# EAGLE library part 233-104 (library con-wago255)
WAGO Cage Clamp

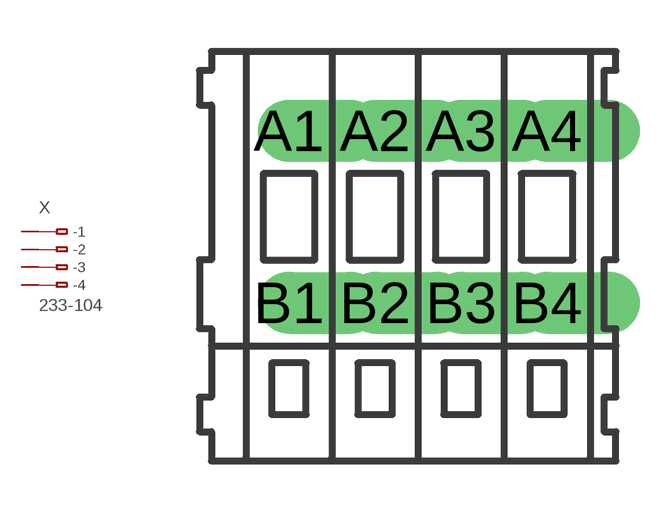
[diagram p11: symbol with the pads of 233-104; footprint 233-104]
Designator prefix X

## 233-104  [233-104]
A1  -1  pas
A2  -2  pas
A3  -3  pas
A4  -4  pas
B1  B-1  pas
B2  B-2  pas
B3  B-3  pas
B4  B-4  pas

## Footprint 233-104 (pad centres in mm)
WAGO Cage Clamp
drill 1.2 offset: A1 -3.75,2.5; A2 -1.25,2.5; A3 1.25,2.5; A4 3.75,2.5; B1 -3.75,-2.5; B2 -1.25,-2.5; B3 1.25,-2.5; B4 3.75,-2.5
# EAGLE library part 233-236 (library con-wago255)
WAGO Cage Clamp

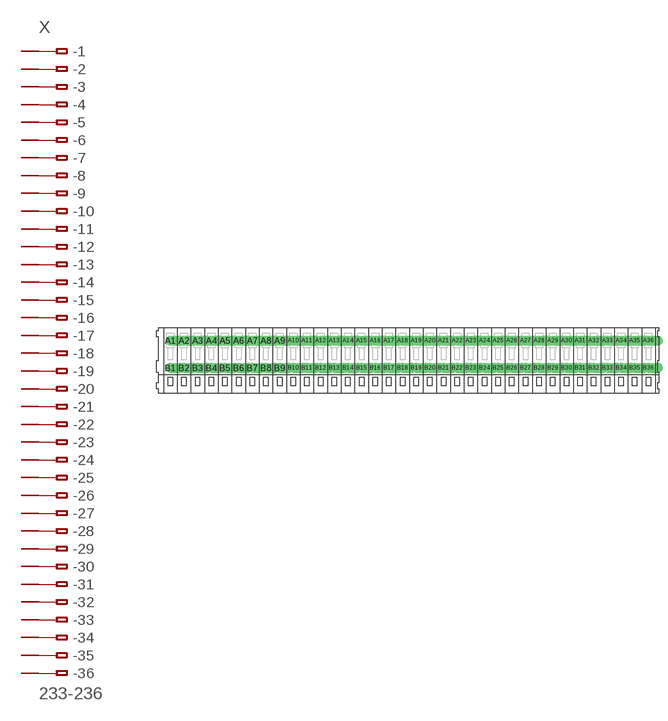
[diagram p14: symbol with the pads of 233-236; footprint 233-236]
Designator prefix X

## 233-236  [233-236]
A1  -1  pas
A2  -2  pas
A3  -3  pas
A4  -4  pas
A5  -5  pas
A6  -6  pas
A7  -7  pas
A8  -8  pas
A9  -9  pas
A10  -10  pas
A11  -11  pas
A12  -12  pas
A13  -13  pas
A14  -14  pas
A15  -15  pas
A16  -16  pas
A17  -17  pas
A18  -18  pas
A19  -19  pas
A20  -20  pas
A21  -21  pas
A22  -22  pas
A23  -23  pas
A24  -24  pas
A25  -25  pas
A26  -26  pas
A27  -27  pas
A28  -28  pas
A29  -29  pas
A30  -30  pas
A31  -31  pas
A32  -32  pas
A33  -33  pas
A34  -34  pas
A35  -35  pas
A36  -36  pas
B1  B-1  pas
B2  B-2  pas
B3  B-3  pas
B4  B-4  pas
B5  B-5  pas
B6  B-6  pas
B7  B-7  pas
B8  B-8  pas
B9  B-9  pas
B10  B-10  pas
B11  B-11  pas
B12  B-12  pas
B13  B-13  pas
B14  B-14  pas
B15  B-15  pas
B16  B-16  pas
B17  B-17  pas
B18  B-18  pas
B19  B-19  pas
B20  B-20  pas
B21  B-21  pas
B22  B-22  pas
B23  B-23  pas
B24  B-24  pas
B25  B-25  pas
B26  B-26  pas
B27  B-27  pas
B28  B-28  pas
B29  B-29  pas
B30  B-30  pas
B31  B-31  pas
B32  B-32  pas
B33  B-33  pas
B34  B-34  pas
B35  B-35  pas
B36  B-36  pas

## Footprint 233-236 (pad centres in mm)
WAGO Cage Clamp
drill 1.2 offset: A1 -43.75,2.5; A2 -41.25,2.5; A3 -38.75,2.5; A4 -36.25,2.5; A5 -33.75,2.5; A6 -31.25,2.5; A7 -28.75,2.5; A8 -26.25,2.5; A9 -23.75,2.5; A10 -21.25,2.5; A11 -18.75,2.5; A12 -16.25,2.5; A13 -13.75,2.5; A14 -11.25,2.5; A15 -8.75,2.5; A16 -6.25,2.5; A17 -3.75,2.5; A18 -1.25,2.5; A19 1.25,2.5; A20 3.75,2.5; A21 6.25,2.5; A22 8.75,2.5; A23 11.25,2.5; A24 13.75,2.5; A25 16.25,2.5; A26 18.75,2.5; A27 21.25,2.5; A28 23.75,2.5; A29 26.25,2.5; A30 28.75,2.5; A31 31.25,2.5; A32 33.75,2.5; A33 36.25,2.5; A34 38.75,2.5; A35 41.25,2.5; A36 43.75,2.5; B1 -43.75,-2.5; B2 -41.25,-2.5; B3 -38.75,-2.5; B4 -36.25,-2.5; B5 -33.75,-2.5; B6 -31.25,-2.5; B7 -28.75,-2.5; B8 -26.25,-2.5; B9 -23.75,-2.5; B10 -21.25,-2.5; B11 -18.75,-2.5; B12 -16.25,-2.5; B13 -13.75,-2.5; B14 -11.25,-2.5; B15 -8.75,-2.5; B16 -6.25,-2.5; B17 -3.75,-2.5; B18 -1.25,-2.5; B19 1.25,-2.5; B20 3.75,-2.5; B21 6.25,-2.5; B22 8.75,-2.5; B23 11.25,-2.5; B24 13.75,-2.5; B25 16.25,-2.5; B26 18.75,-2.5; B27 21.25,-2.5; B28 23.75,-2.5; B29 26.25,-2.5; B30 28.75,-2.5; B31 31.25,-2.5; B32 33.75,-2.5; B33 36.25,-2.5; B34 38.75,-2.5; B35 41.25,-2.5; B36 43.75,-2.5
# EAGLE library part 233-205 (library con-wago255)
WAGO Cage Clamp

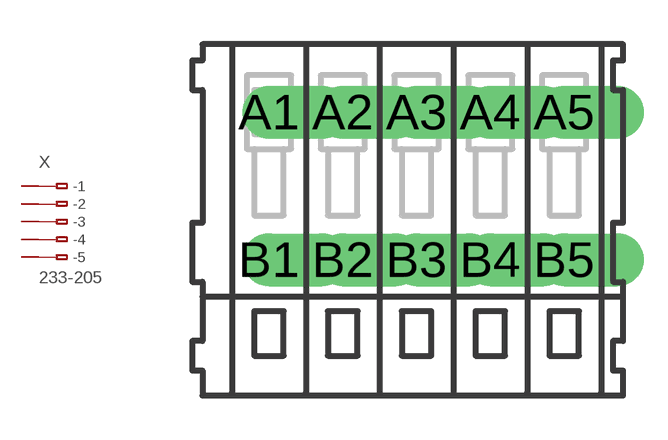
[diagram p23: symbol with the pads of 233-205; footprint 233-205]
Designator prefix X

## 233-205  [233-205]
A1  -1  pas
A2  -2  pas
A3  -3  pas
A4  -4  pas
A5  -5  pas
B1  B-1  pas
B2  B-2  pas
B3  B-3  pas
B4  B-4  pas
B5  B-5  pas

## Footprint 233-205 (pad centres in mm)
WAGO Cage Clamp
drill 1.2 offset: A1 -5,2.5; A2 -2.5,2.5; A3 0,2.5; A4 2.5,2.5; A5 5,2.5; B1 -5,-2.5; B2 -2.5,-2.5; B3 0,-2.5; B4 2.5,-2.5; B5 5,-2.5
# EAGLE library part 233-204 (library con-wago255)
WAGO Cage Clamp

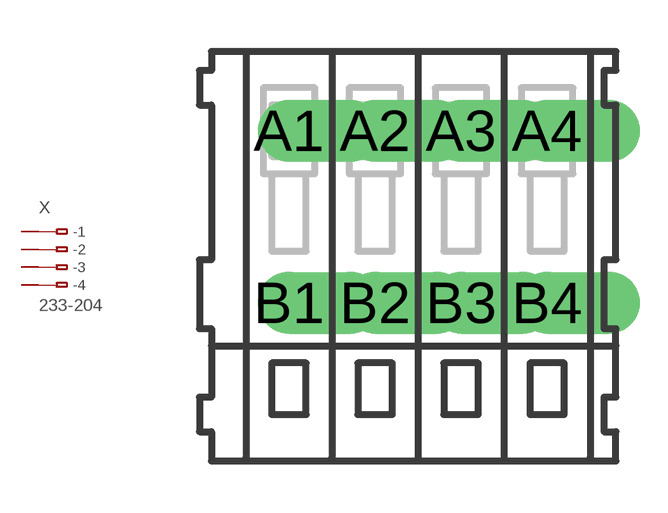
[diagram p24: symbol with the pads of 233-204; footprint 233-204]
Designator prefix X

## 233-204  [233-204]
A1  -1  pas
A2  -2  pas
A3  -3  pas
A4  -4  pas
B1  B-1  pas
B2  B-2  pas
B3  B-3  pas
B4  B-4  pas

## Footprint 233-204 (pad centres in mm)
WAGO Cage Clamp
drill 1.2 offset: A1 -3.75,2.5; A2 -1.25,2.5; A3 1.25,2.5; A4 3.75,2.5; B1 -3.75,-2.5; B2 -1.25,-2.5; B3 1.25,-2.5; B4 3.75,-2.5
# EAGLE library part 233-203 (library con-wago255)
WAGO Cage Clamp

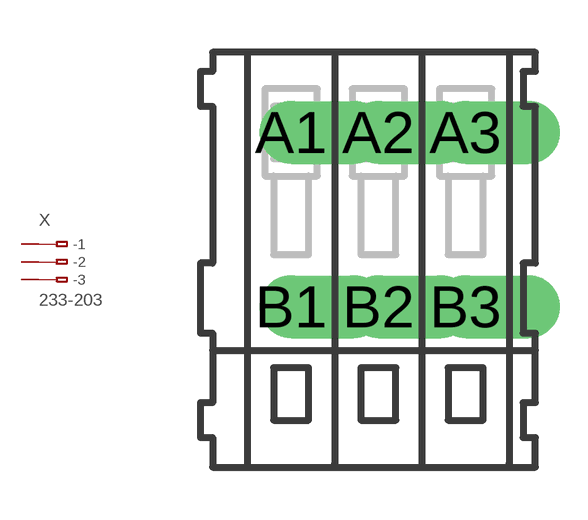
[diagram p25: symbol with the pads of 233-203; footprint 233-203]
Designator prefix X

## 233-203  [233-203]
A1  -1  pas
A2  -2  pas
A3  -3  pas
B1  B-1  pas
B2  B-2  pas
B3  B-3  pas

## Footprint 233-203 (pad centres in mm)
WAGO Cage Clamp
drill 1.2 offset: A1 -2.5,2.5; A2 0,2.5; A3 2.5,2.5; B1 -2.5,-2.5; B2 0,-2.5; B3 2.5,-2.5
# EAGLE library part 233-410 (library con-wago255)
WAGO Cage Clamp

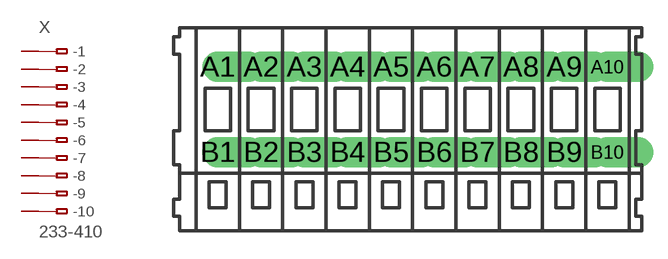
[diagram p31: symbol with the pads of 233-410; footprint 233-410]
Designator prefix X

## 233-410  [233-410]
A1  -1  pas
A2  -2  pas
A3  -3  pas
A4  -4  pas
A5  -5  pas
A6  -6  pas
A7  -7  pas
A8  -8  pas
A9  -9  pas
A10  -10  pas
B1  B-1  pas
B2  B-2  pas
B3  B-3  pas
B4  B-4  pas
B5  B-5  pas
B6  B-6  pas
B7  B-7  pas
B8  B-8  pas
B9  B-9  pas
B10  B-10  pas

## Footprint 233-410 (pad centres in mm)
WAGO Cage Clamp
drill 1.2 offset: A1 -11.43,2.5; A2 -8.89,2.5; A3 -6.35,2.5; A4 -3.81,2.5; A5 -1.27,2.5; A6 1.27,2.5; A7 3.81,2.5; A8 6.35,2.5; A9 8.89,2.5; A10 11.43,2.5; B1 -11.43,-2.5; B2 -8.89,-2.5; B3 -6.35,-2.5; B4 -3.81,-2.5; B5 -1.27,-2.5; B6 1.27,-2.5; B7 3.81,-2.5; B8 6.35,-2.5; B9 8.89,-2.5; B10 11.43,-2.5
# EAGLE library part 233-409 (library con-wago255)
WAGO Cage Clamp

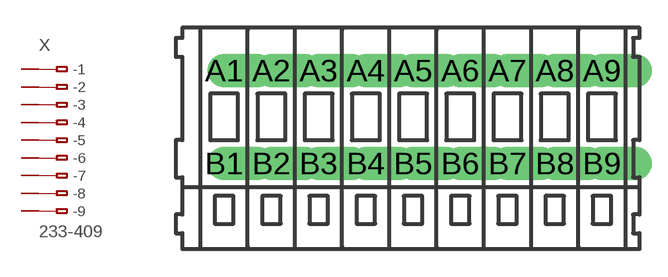
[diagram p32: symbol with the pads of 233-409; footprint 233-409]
Designator prefix X

## 233-409  [233-409]
A1  -1  pas
A2  -2  pas
A3  -3  pas
A4  -4  pas
A5  -5  pas
A6  -6  pas
A7  -7  pas
A8  -8  pas
A9  -9  pas
B1  B-1  pas
B2  B-2  pas
B3  B-3  pas
B4  B-4  pas
B5  B-5  pas
B6  B-6  pas
B7  B-7  pas
B8  B-8  pas
B9  B-9  pas

## Footprint 233-409 (pad centres in mm)
WAGO Cage Clamp
drill 1.2 offset: A1 -10.16,2.5; A2 -7.62,2.5; A3 -5.08,2.5; A4 -2.54,2.5; A5 0,2.5; A6 2.54,2.5; A7 5.08,2.5; A8 7.62,2.5; A9 10.16,2.5; B1 -10.16,-2.5; B2 -7.62,-2.5; B3 -5.08,-2.5; B4 -2.54,-2.5; B5 0,-2.5; B6 2.54,-2.5; B7 5.08,-2.5; B8 7.62,-2.5; B9 10.16,-2.5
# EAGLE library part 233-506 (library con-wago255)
WAGO Cage Clamp

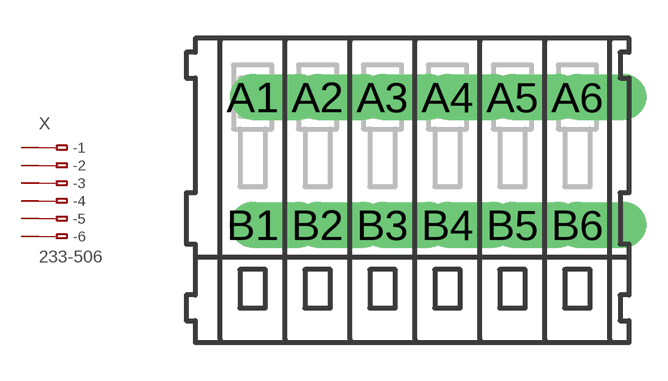
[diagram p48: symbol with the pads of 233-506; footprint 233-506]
Designator prefix X

## 233-506  [233-506]
A1  -1  pas
A2  -2  pas
A3  -3  pas
A4  -4  pas
A5  -5  pas
A6  -6  pas
B1  B-1  pas
B2  B-2  pas
B3  B-3  pas
B4  B-4  pas
B5  B-5  pas
B6  B-6  pas

## Footprint 233-506 (pad centres in mm)
WAGO Cage Clamp
drill 1.2 offset: A1 -6.35,2.5; A2 -3.81,2.5; A3 -1.27,2.5; A4 1.27,2.5; A5 3.81,2.5; A6 6.35,2.5; B1 -6.35,-2.5; B2 -3.81,-2.5; B3 -1.27,-2.5; B4 1.27,-2.5; B5 3.81,-2.5; B6 6.35,-2.5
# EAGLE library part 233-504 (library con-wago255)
WAGO Cage Clamp

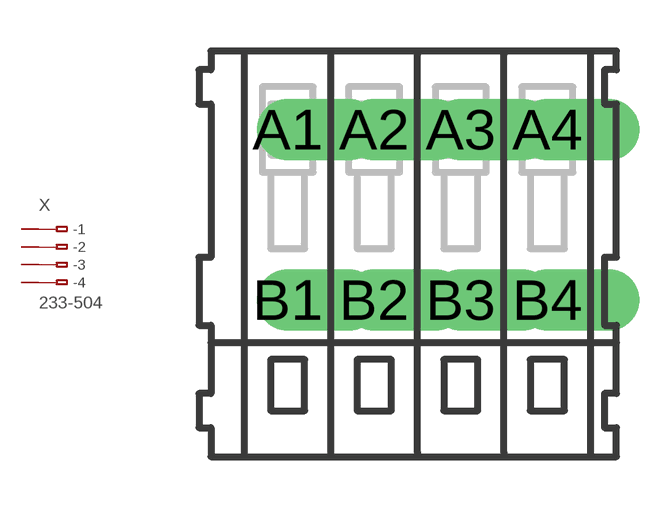
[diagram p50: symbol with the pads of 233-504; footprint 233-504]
Designator prefix X

## 233-504  [233-504]
A1  -1  pas
A2  -2  pas
A3  -3  pas
A4  -4  pas
B1  B-1  pas
B2  B-2  pas
B3  B-3  pas
B4  B-4  pas

## Footprint 233-504 (pad centres in mm)
WAGO Cage Clamp
drill 1.2 offset: A1 -3.81,2.5; A2 -1.27,2.5; A3 1.27,2.5; A4 3.81,2.5; B1 -3.81,-2.5; B2 -1.27,-2.5; B3 1.27,-2.5; B4 3.81,-2.5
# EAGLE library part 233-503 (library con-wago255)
WAGO Cage Clamp

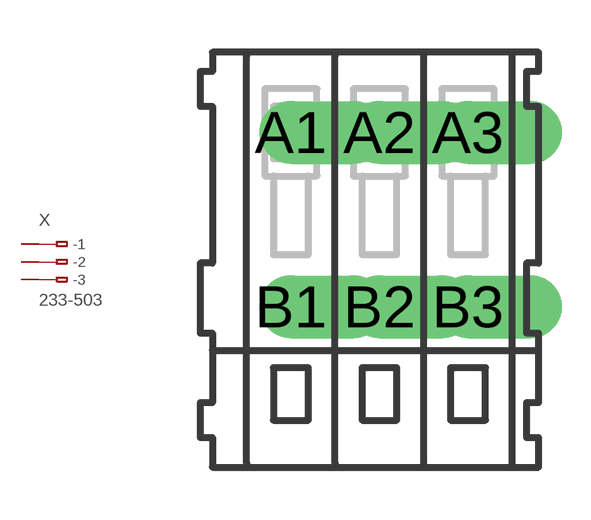
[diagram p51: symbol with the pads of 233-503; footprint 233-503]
Designator prefix X

## 233-503  [233-503]
A1  -1  pas
A2  -2  pas
A3  -3  pas
B1  B-1  pas
B2  B-2  pas
B3  B-3  pas

## Footprint 233-503 (pad centres in mm)
WAGO Cage Clamp
drill 1.2 offset: A1 -2.54,2.5; A2 0,2.5; A3 2.54,2.5; B1 -2.54,-2.5; B2 0,-2.5; B3 2.54,-2.5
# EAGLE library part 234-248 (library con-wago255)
WAGO Cage Clamp

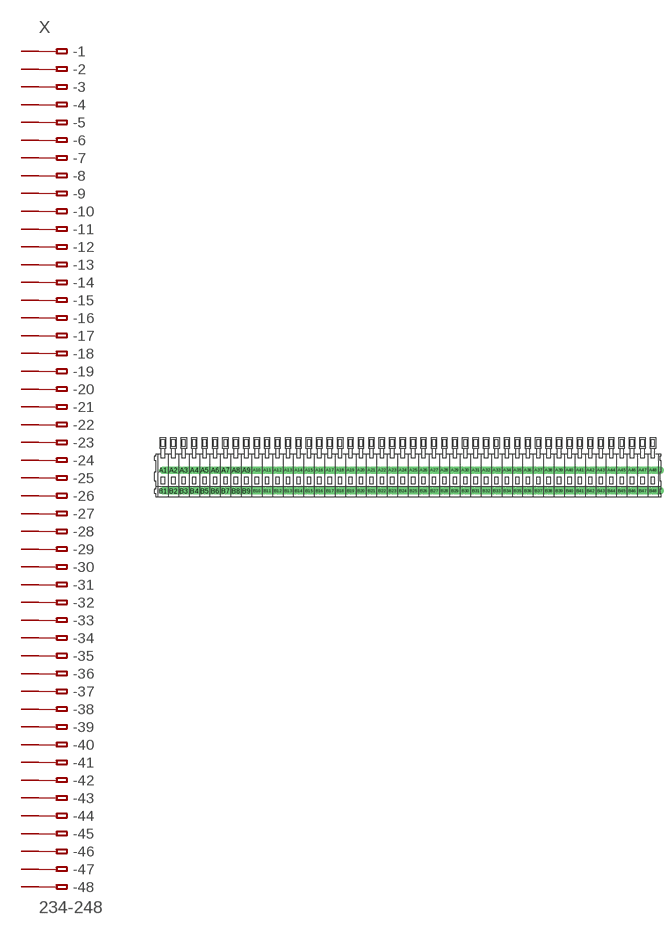
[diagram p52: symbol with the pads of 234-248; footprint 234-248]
Designator prefix X

## 234-248  [234-248]
A1  -1  pas
A2  -2  pas
A3  -3  pas
A4  -4  pas
A5  -5  pas
A6  -6  pas
A7  -7  pas
A8  -8  pas
A9  -9  pas
A10  -10  pas
A11  -11  pas
A12  -12  pas
A13  -13  pas
A14  -14  pas
A15  -15  pas
A16  -16  pas
A17  -17  pas
A18  -18  pas
A19  -19  pas
A20  -20  pas
A21  -21  pas
A22  -22  pas
A23  -23  pas
A24  -24  pas
A25  -25  pas
A26  -26  pas
A27  -27  pas
A28  -28  pas
A29  -29  pas
A30  -30  pas
A31  -31  pas
A32  -32  pas
A33  -33  pas
A34  -34  pas
A35  -35  pas
A36  -36  pas
A37  -37  pas
A38  -38  pas
A39  -39  pas
A40  -40  pas
A41  -41  pas
A42  -42  pas
A43  -43  pas
A44  -44  pas
A45  -45  pas
A46  -46  pas
A47  -47  pas
A48  -48  pas
B1  B-1  pas
B2  B-2  pas
B3  B-3  pas
B4  B-4  pas
B5  B-5  pas
B6  B-6  pas
B7  B-7  pas
B8  B-8  pas
B9  B-9  pas
B10  B-10  pas
B11  B-11  pas
B12  B-12  pas
B13  B-13  pas
B14  B-14  pas
B15  B-15  pas
B16  B-16  pas
B17  B-17  pas
B18  B-18  pas
B19  B-19  pas
B20  B-20  pas
B21  B-21  pas
B22  B-22  pas
B23  B-23  pas
B24  B-24  pas
B25  B-25  pas
B26  B-26  pas
B27  B-27  pas
B28  B-28  pas
B29  B-29  pas
B30  B-30  pas
B31  B-31  pas
B32  B-32  pas
B33  B-33  pas
B34  B-34  pas
B35  B-35  pas
B36  B-36  pas
B37  B-37  pas
B38  B-38  pas
B39  B-39  pas
B40  B-40  pas
B41  B-41  pas
B42  B-42  pas
B43  B-43  pas
B44  B-44  pas
B45  B-45  pas
B46  B-46  pas
B47  B-47  pas
B48  B-48  pas

## Footprint 234-248 (pad centres in mm)
WAGO Cage Clamp
drill 1.2 offset: A1 -58.75,2.5; A2 -56.25,2.5; A3 -53.75,2.5; A4 -51.25,2.5; A5 -48.75,2.5; A6 -46.25,2.5; A7 -43.75,2.5; A8 -41.25,2.5; A9 -38.75,2.5; A10 -36.25,2.5; A11 -33.75,2.5; A12 -31.25,2.5; A13 -28.75,2.5; A14 -26.25,2.5; A15 -23.75,2.5; A16 -21.25,2.5; A17 -18.75,2.5; A18 -16.25,2.5; A19 -13.75,2.5; A20 -11.25,2.5; A21 -8.75,2.5; A22 -6.25,2.5; A23 -3.75,2.5; A24 -1.25,2.5; A25 1.25,2.5; A26 3.75,2.5; A27 6.25,2.5; A28 8.75,2.5; A29 11.25,2.5; A30 13.75,2.5; A31 16.25,2.5; A32 18.75,2.5; A33 21.25,2.5; A34 23.75,2.5; A35 26.25,2.5; A36 28.75,2.5; A37 31.25,2.5; A38 33.75,2.5; A39 36.25,2.5; A40 38.75,2.5; A41 41.25,2.5; A42 43.75,2.5; A43 46.25,2.5; A44 48.75,2.5; A45 51.25,2.5; A46 53.75,2.5; A47 56.25,2.5; A48 58.75,2.5; B1 -58.75,-2.5; B2 -56.25,-2.5; B3 -53.75,-2.5; B4 -51.25,-2.5; B5 -48.75,-2.5; B6 -46.25,-2.5; B7 -43.75,-2.5; B8 -41.25,-2.5; B9 -38.75,-2.5; B10 -36.25,-2.5; B11 -33.75,-2.5; B12 -31.25,-2.5; B13 -28.75,-2.5; B14 -26.25,-2.5; B15 -23.75,-2.5; B16 -21.25,-2.5; B17 -18.75,-2.5; B18 -16.25,-2.5; B19 -13.75,-2.5; B20 -11.25,-2.5; B21 -8.75,-2.5; B22 -6.25,-2.5; B23 -3.75,-2.5; B24 -1.25,-2.5; B25 1.25,-2.5; B26 3.75,-2.5; B27 6.25,-2.5; B28 8.75,-2.5; B29 11.25,-2.5; B30 13.75,-2.5; B31 16.25,-2.5; B32 18.75,-2.5; B33 21.25,-2.5; B34 23.75,-2.5; B35 26.25,-2.5; B36 28.75,-2.5; B37 31.25,-2.5; B38 33.75,-2.5; B39 36.25,-2.5; B40 38.75,-2.5; B41 41.25,-2.5; B42 43.75,-2.5; B43 46.25,-2.5; B44 48.75,-2.5; B45 51.25,-2.5; B46 53.75,-2.5; B47 56.25,-2.5; B48 58.75,-2.5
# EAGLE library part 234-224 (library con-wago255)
WAGO Cage Clamp

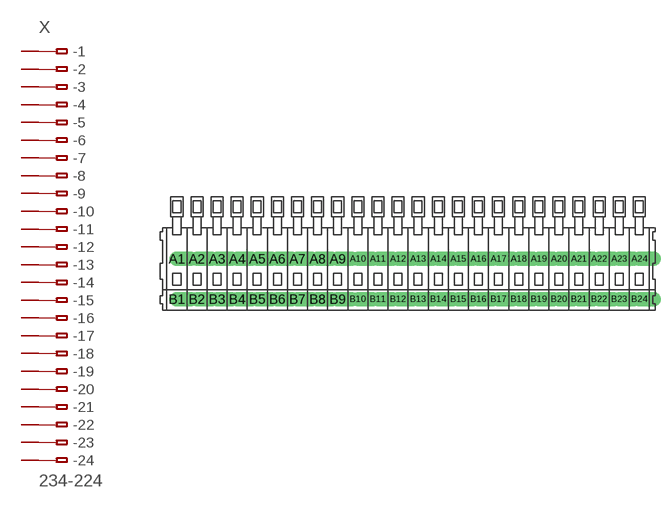
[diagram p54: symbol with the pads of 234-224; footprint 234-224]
Designator prefix X

## 234-224  [234-224]
A1  -1  pas
A2  -2  pas
A3  -3  pas
A4  -4  pas
A5  -5  pas
A6  -6  pas
A7  -7  pas
A8  -8  pas
A9  -9  pas
A10  -10  pas
A11  -11  pas
A12  -12  pas
A13  -13  pas
A14  -14  pas
A15  -15  pas
A16  -16  pas
A17  -17  pas
A18  -18  pas
A19  -19  pas
A20  -20  pas
A21  -21  pas
A22  -22  pas
A23  -23  pas
A24  -24  pas
B1  B-1  pas
B2  B-2  pas
B3  B-3  pas
B4  B-4  pas
B5  B-5  pas
B6  B-6  pas
B7  B-7  pas
B8  B-8  pas
B9  B-9  pas
B10  B-10  pas
B11  B-11  pas
B12  B-12  pas
B13  B-13  pas
B14  B-14  pas
B15  B-15  pas
B16  B-16  pas
B17  B-17  pas
B18  B-18  pas
B19  B-19  pas
B20  B-20  pas
B21  B-21  pas
B22  B-22  pas
B23  B-23  pas
B24  B-24  pas

## Footprint 234-224 (pad centres in mm)
WAGO Cage Clamp
drill 1.2 offset: A1 -28.75,2.5; A2 -26.25,2.5; A3 -23.75,2.5; A4 -21.25,2.5; A5 -18.75,2.5; A6 -16.25,2.5; A7 -13.75,2.5; A8 -11.25,2.5; A9 -8.75,2.5; A10 -6.25,2.5; A11 -3.75,2.5; A12 -1.25,2.5; A13 1.25,2.5; A14 3.75,2.5; A15 6.25,2.5; A16 8.75,2.5; A17 11.25,2.5; A18 13.75,2.5; A19 16.25,2.5; A20 18.75,2.5; A21 21.25,2.5; A22 23.75,2.5; A23 26.25,2.5; A24 28.75,2.5; B1 -28.75,-2.5; B2 -26.25,-2.5; B3 -23.75,-2.5; B4 -21.25,-2.5; B5 -18.75,-2.5; B6 -16.25,-2.5; B7 -13.75,-2.5; B8 -11.25,-2.5; B9 -8.75,-2.5; B10 -6.25,-2.5; B11 -3.75,-2.5; B12 -1.25,-2.5; B13 1.25,-2.5; B14 3.75,-2.5; B15 6.25,-2.5; B16 8.75,-2.5; B17 11.25,-2.5; B18 13.75,-2.5; B19 16.25,-2.5; B20 18.75,-2.5; B21 21.25,-2.5; B22 23.75,-2.5; B23 26.25,-2.5; B24 28.75,-2.5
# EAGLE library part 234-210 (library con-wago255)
WAGO Cage Clamp

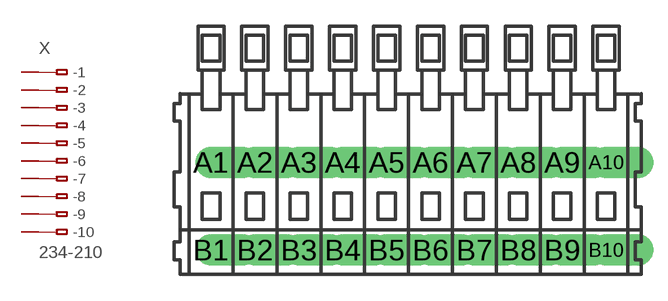
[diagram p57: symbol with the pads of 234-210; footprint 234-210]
Designator prefix X

## 234-210  [234-210]
A1  -1  pas
A2  -2  pas
A3  -3  pas
A4  -4  pas
A5  -5  pas
A6  -6  pas
A7  -7  pas
A8  -8  pas
A9  -9  pas
A10  -10  pas
B1  B-1  pas
B2  B-2  pas
B3  B-3  pas
B4  B-4  pas
B5  B-5  pas
B6  B-6  pas
B7  B-7  pas
B8  B-8  pas
B9  B-9  pas
B10  B-10  pas

## Footprint 234-210 (pad centres in mm)
WAGO Cage Clamp
drill 1.2 offset: A1 -11.25,2.5; A2 -8.75,2.5; A3 -6.25,2.5; A4 -3.75,2.5; A5 -1.25,2.5; A6 1.25,2.5; A7 3.75,2.5; A8 6.25,2.5; A9 8.75,2.5; A10 11.25,2.5; B1 -11.25,-2.5; B2 -8.75,-2.5; B3 -6.25,-2.5; B4 -3.75,-2.5; B5 -1.25,-2.5; B6 1.25,-2.5; B7 3.75,-2.5; B8 6.25,-2.5; B9 8.75,-2.5; B10 11.25,-2.5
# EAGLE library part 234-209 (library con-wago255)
WAGO Cage Clamp

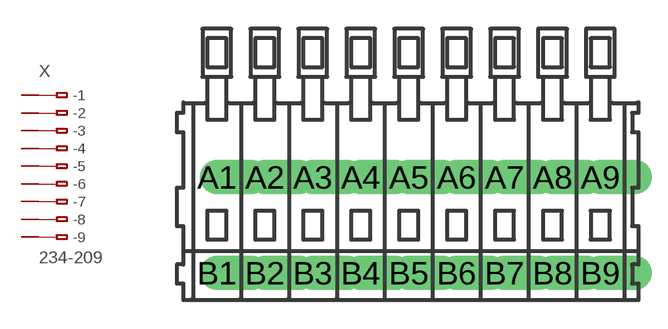
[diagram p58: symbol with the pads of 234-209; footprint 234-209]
Designator prefix X

## 234-209  [234-209]
A1  -1  pas
A2  -2  pas
A3  -3  pas
A4  -4  pas
A5  -5  pas
A6  -6  pas
A7  -7  pas
A8  -8  pas
A9  -9  pas
B1  B-1  pas
B2  B-2  pas
B3  B-3  pas
B4  B-4  pas
B5  B-5  pas
B6  B-6  pas
B7  B-7  pas
B8  B-8  pas
B9  B-9  pas

## Footprint 234-209 (pad centres in mm)
WAGO Cage Clamp
drill 1.2 offset: A1 -10,2.5; A2 -7.5,2.5; A3 -5,2.5; A4 -2.5,2.5; A5 0,2.5; A6 2.5,2.5; A7 5,2.5; A8 7.5,2.5; A9 10,2.5; B1 -10,-2.5; B2 -7.5,-2.5; B3 -5,-2.5; B4 -2.5,-2.5; B5 0,-2.5; B6 2.5,-2.5; B7 5,-2.5; B8 7.5,-2.5; B9 10,-2.5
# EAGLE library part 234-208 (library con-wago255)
WAGO Cage Clamp

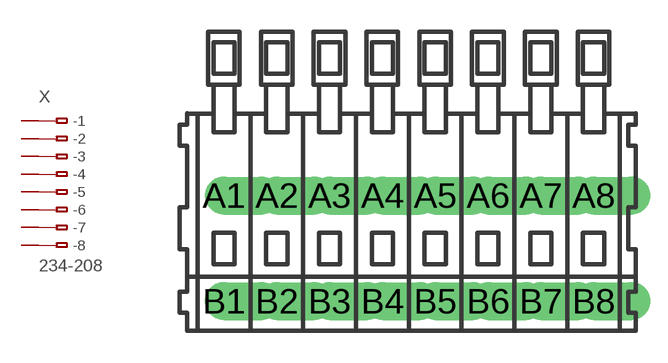
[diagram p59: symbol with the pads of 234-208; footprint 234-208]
Designator prefix X

## 234-208  [234-208]
A1  -1  pas
A2  -2  pas
A3  -3  pas
A4  -4  pas
A5  -5  pas
A6  -6  pas
A7  -7  pas
A8  -8  pas
B1  B-1  pas
B2  B-2  pas
B3  B-3  pas
B4  B-4  pas
B5  B-5  pas
B6  B-6  pas
B7  B-7  pas
B8  B-8  pas

## Footprint 234-208 (pad centres in mm)
WAGO Cage Clamp
drill 1.2 offset: A1 -8.75,2.5; A2 -6.25,2.5; A3 -3.75,2.5; A4 -1.25,2.5; A5 1.25,2.5; A6 3.75,2.5; A7 6.25,2.5; A8 8.75,2.5; B1 -8.75,-2.5; B2 -6.25,-2.5; B3 -3.75,-2.5; B4 -1.25,-2.5; B5 1.25,-2.5; B6 3.75,-2.5; B7 6.25,-2.5; B8 8.75,-2.5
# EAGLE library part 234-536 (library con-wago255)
WAGO Cage Clamp

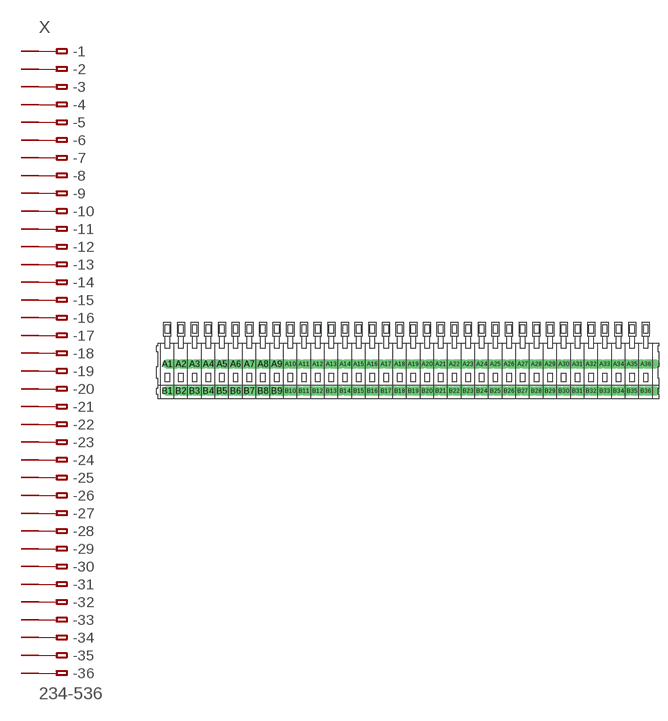
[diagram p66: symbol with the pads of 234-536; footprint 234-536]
Designator prefix X

## 234-536  [234-536]
A1  -1  pas
A2  -2  pas
A3  -3  pas
A4  -4  pas
A5  -5  pas
A6  -6  pas
A7  -7  pas
A8  -8  pas
A9  -9  pas
A10  -10  pas
A11  -11  pas
A12  -12  pas
A13  -13  pas
A14  -14  pas
A15  -15  pas
A16  -16  pas
A17  -17  pas
A18  -18  pas
A19  -19  pas
A20  -20  pas
A21  -21  pas
A22  -22  pas
A23  -23  pas
A24  -24  pas
A25  -25  pas
A26  -26  pas
A27  -27  pas
A28  -28  pas
A29  -29  pas
A30  -30  pas
A31  -31  pas
A32  -32  pas
A33  -33  pas
A34  -34  pas
A35  -35  pas
A36  -36  pas
B1  B-1  pas
B2  B-2  pas
B3  B-3  pas
B4  B-4  pas
B5  B-5  pas
B6  B-6  pas
B7  B-7  pas
B8  B-8  pas
B9  B-9  pas
B10  B-10  pas
B11  B-11  pas
B12  B-12  pas
B13  B-13  pas
B14  B-14  pas
B15  B-15  pas
B16  B-16  pas
B17  B-17  pas
B18  B-18  pas
B19  B-19  pas
B20  B-20  pas
B21  B-21  pas
B22  B-22  pas
B23  B-23  pas
B24  B-24  pas
B25  B-25  pas
B26  B-26  pas
B27  B-27  pas
B28  B-28  pas
B29  B-29  pas
B30  B-30  pas
B31  B-31  pas
B32  B-32  pas
B33  B-33  pas
B34  B-34  pas
B35  B-35  pas
B36  B-36  pas

## Footprint 234-536 (pad centres in mm)
WAGO Cage Clamp
drill 1.2 offset: A1 -44.45,1.23; A2 -41.91,1.23; A3 -39.37,1.23; A4 -36.83,1.23; A5 -34.29,1.23; A6 -31.75,1.23; A7 -29.21,1.23; A8 -26.67,1.23; A9 -24.13,1.23; A10 -21.59,1.23; A11 -19.05,1.23; A12 -16.51,1.23; A13 -13.97,1.23; A14 -11.43,1.23; A15 -8.89,1.23; A16 -6.35,1.23; A17 -3.81,1.23; A18 -1.27,1.23; A19 1.27,1.23; A20 3.81,1.23; A21 6.35,1.23; A22 8.89,1.23; A23 11.43,1.23; A24 13.97,1.23; A25 16.51,1.23; A26 19.05,1.23; A27 21.59,1.23; A28 24.13,1.23; A29 26.67,1.23; A30 29.21,1.23; A31 31.75,1.23; A32 34.29,1.23; A33 36.83,1.23; A34 39.37,1.23; A35 41.91,1.23; A36 44.45,1.23; B1 -44.45,-3.77; B2 -41.91,-3.77; B3 -39.37,-3.77; B4 -36.83,-3.77; B5 -34.29,-3.77; B6 -31.75,-3.77; B7 -29.21,-3.77; B8 -26.67,-3.77; B9 -24.13,-3.77; B10 -21.59,-3.77; B11 -19.05,-3.77; B12 -16.51,-3.77; B13 -13.97,-3.77; B14 -11.43,-3.77; B15 -8.89,-3.77; B16 -6.35,-3.77; B17 -3.81,-3.77; B18 -1.27,-3.77; B19 1.27,-3.77; B20 3.81,-3.77; B21 6.35,-3.77; B22 8.89,-3.77; B23 11.43,-3.77; B24 13.97,-3.77; B25 16.51,-3.77; B26 19.05,-3.77; B27 21.59,-3.77; B28 24.13,-3.77; B29 26.67,-3.77; B30 29.21,-3.77; B31 31.75,-3.77; B32 34.29,-3.77; B33 36.83,-3.77; B34 39.37,-3.77; B35 41.91,-3.77; B36 44.45,-3.77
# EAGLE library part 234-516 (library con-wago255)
WAGO Cage Clamp

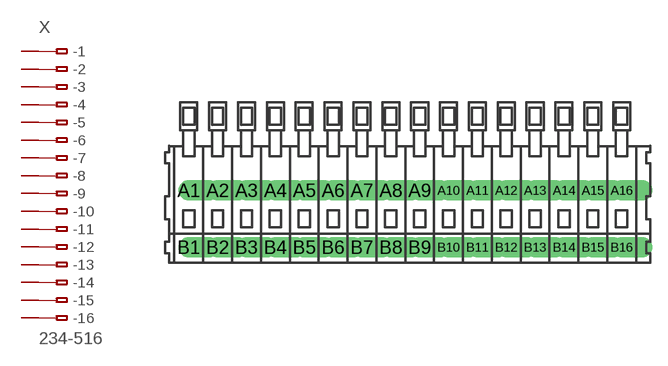
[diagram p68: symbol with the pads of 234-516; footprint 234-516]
Designator prefix X

## 234-516  [234-516]
A1  -1  pas
A2  -2  pas
A3  -3  pas
A4  -4  pas
A5  -5  pas
A6  -6  pas
A7  -7  pas
A8  -8  pas
A9  -9  pas
A10  -10  pas
A11  -11  pas
A12  -12  pas
A13  -13  pas
A14  -14  pas
A15  -15  pas
A16  -16  pas
B1  B-1  pas
B2  B-2  pas
B3  B-3  pas
B4  B-4  pas
B5  B-5  pas
B6  B-6  pas
B7  B-7  pas
B8  B-8  pas
B9  B-9  pas
B10  B-10  pas
B11  B-11  pas
B12  B-12  pas
B13  B-13  pas
B14  B-14  pas
B15  B-15  pas
B16  B-16  pas

## Footprint 234-516 (pad centres in mm)
WAGO Cage Clamp
drill 1.2 offset: A1 -19.05,2.5; A2 -16.51,2.5; A3 -13.97,2.5; A4 -11.43,2.5; A5 -8.89,2.5; A6 -6.35,2.5; A7 -3.81,2.5; A8 -1.27,2.5; A9 1.27,2.5; A10 3.81,2.5; A11 6.35,2.5; A12 8.89,2.5; A13 11.43,2.5; A14 13.97,2.5; A15 16.51,2.5; A16 19.05,2.5; B1 -19.05,-2.5; B2 -16.51,-2.5; B3 -13.97,-2.5; B4 -11.43,-2.5; B5 -8.89,-2.5; B6 -6.35,-2.5; B7 -3.81,-2.5; B8 -1.27,-2.5; B9 1.27,-2.5; B10 3.81,-2.5; B11 6.35,-2.5; B12 8.89,-2.5; B13 11.43,-2.5; B14 13.97,-2.5; B15 16.51,-2.5; B16 19.05,-2.5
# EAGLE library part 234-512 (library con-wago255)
WAGO Cage Clamp

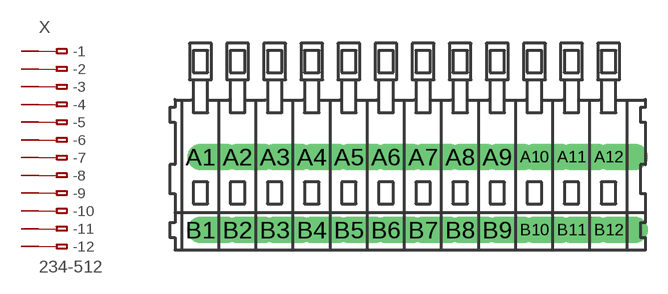
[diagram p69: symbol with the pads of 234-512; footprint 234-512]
Designator prefix X

## 234-512  [234-512]
A1  -1  pas
A2  -2  pas
A3  -3  pas
A4  -4  pas
A5  -5  pas
A6  -6  pas
A7  -7  pas
A8  -8  pas
A9  -9  pas
A10  -10  pas
A11  -11  pas
A12  -12  pas
B1  B-1  pas
B2  B-2  pas
B3  B-3  pas
B4  B-4  pas
B5  B-5  pas
B6  B-6  pas
B7  B-7  pas
B8  B-8  pas
B9  B-9  pas
B10  B-10  pas
B11  B-11  pas
B12  B-12  pas

## Footprint 234-512 (pad centres in mm)
WAGO Cage Clamp
drill 1.2 offset: A1 -13.97,2.5; A2 -11.43,2.5; A3 -8.89,2.5; A4 -6.35,2.5; A5 -3.81,2.5; A6 -1.27,2.5; A7 1.27,2.5; A8 3.81,2.5; A9 6.35,2.5; A10 8.89,2.5; A11 11.43,2.5; A12 13.97,2.5; B1 -13.97,-2.5; B2 -11.43,-2.5; B3 -8.89,-2.5; B4 -6.35,-2.5; B5 -3.81,-2.5; B6 -1.27,-2.5; B7 1.27,-2.5; B8 3.81,-2.5; B9 6.35,-2.5; B10 8.89,-2.5; B11 11.43,-2.5; B12 13.97,-2.5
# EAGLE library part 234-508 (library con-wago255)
WAGO Cage Clamp

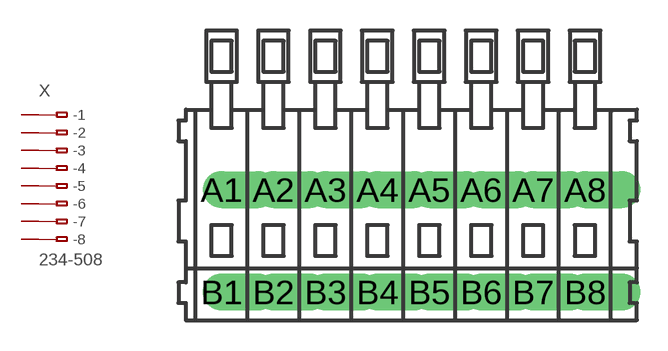
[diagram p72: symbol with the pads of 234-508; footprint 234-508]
Designator prefix X

## 234-508  [234-508]
A1  -1  pas
A2  -2  pas
A3  -3  pas
A4  -4  pas
A5  -5  pas
A6  -6  pas
A7  -7  pas
A8  -8  pas
B1  B-1  pas
B2  B-2  pas
B3  B-3  pas
B4  B-4  pas
B5  B-5  pas
B6  B-6  pas
B7  B-7  pas
B8  B-8  pas

## Footprint 234-508 (pad centres in mm)
WAGO Cage Clamp
drill 1.2 offset: A1 -8.89,2.5; A2 -6.35,2.5; A3 -3.81,2.5; A4 -1.27,2.5; A5 1.27,2.5; A6 3.81,2.5; A7 6.35,2.5; A8 8.89,2.5; B1 -8.89,-2.5; B2 -6.35,-2.5; B3 -3.81,-2.5; B4 -1.27,-2.5; B5 1.27,-2.5; B6 3.81,-2.5; B7 6.35,-2.5; B8 8.89,-2.5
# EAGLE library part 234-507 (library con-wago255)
WAGO Cage Clamp

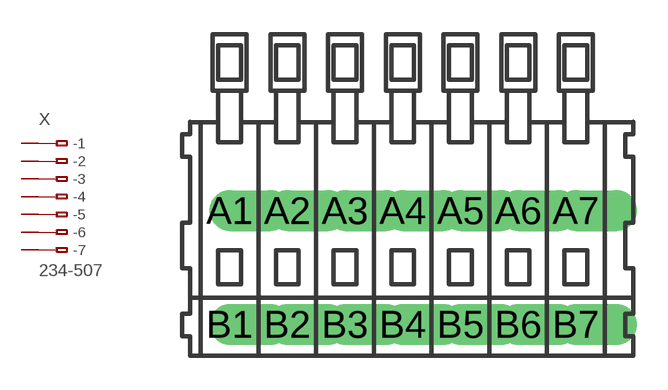
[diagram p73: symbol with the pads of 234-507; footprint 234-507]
Designator prefix X

## 234-507  [234-507]
A1  -1  pas
A2  -2  pas
A3  -3  pas
A4  -4  pas
A5  -5  pas
A6  -6  pas
A7  -7  pas
B1  B-1  pas
B2  B-2  pas
B3  B-3  pas
B4  B-4  pas
B5  B-5  pas
B6  B-6  pas
B7  B-7  pas

## Footprint 234-507 (pad centres in mm)
WAGO Cage Clamp
drill 1.2 offset: A1 -7.62,2.5; A2 -5.08,2.5; A3 -2.54,2.5; A4 0,2.5; A5 2.54,2.5; A6 5.08,2.5; A7 7.62,2.5; B1 -7.62,-2.5; B2 -5.08,-2.5; B3 -2.54,-2.5; B4 0,-2.5; B5 2.54,-2.5; B6 5.08,-2.5; B7 7.62,-2.5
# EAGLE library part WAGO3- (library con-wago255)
WAGO Cage Clamp

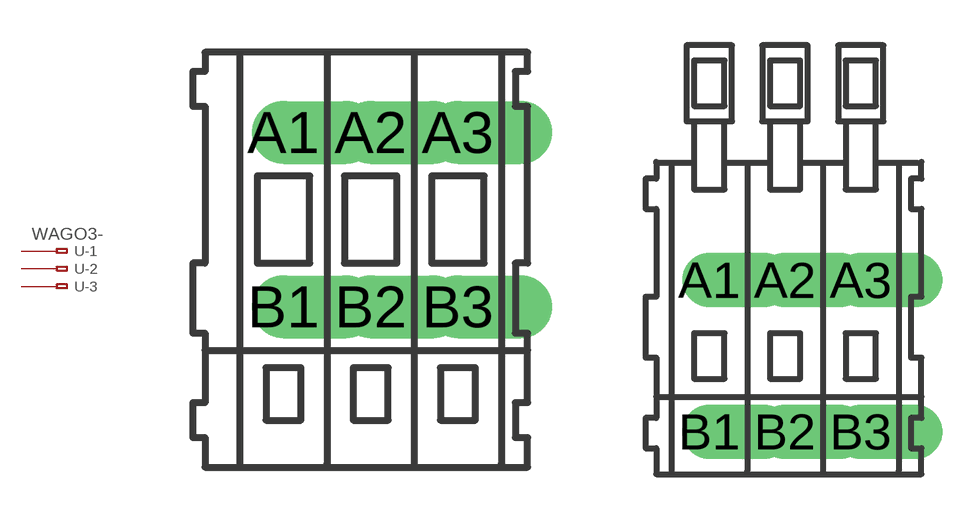
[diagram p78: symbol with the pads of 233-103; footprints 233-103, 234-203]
Designator prefix -; gates -1=KL-1V -2=KL-1 -3=KL-1

## WAGO3-233-103  [233-103]
A1  -1:A1  pas
A2  -2:A1  pas
A3  -3:A1  pas
B1  -1:B1  pas
B2  -2:B1  pas
B3  -3:B1  pas

## WAGO3-234-203  [234-203]
Pads as for 233-103

## WAGO3-255-403-1000  [255-403-1000]
Pads as for 233-103

## WAGO3-255-403-1016  [255-403-1016]
Pads as for 233-103

## WAGO3-255-403-5  [255-403-5]
Pads as for 233-103

## WAGO3-255-403-508  [255-403-508]
Pads as for 233-103

## WAGO3-255-403-750  [255-403-750]
Pads as for 233-103

## WAGO3-255-403-762  [255-403-762]
Pads as for 233-103

## Footprint 233-103 (pad centres in mm)
WAGO Cage Clamp
drill 1.2 offset: A1 -2.5,2.5; A2 0,2.5; A3 2.5,2.5; B1 -2.5,-2.5; B2 0,-2.5; B3 2.5,-2.5

## Footprint 234-203 (pad centres in mm)
WAGO Cage Clamp
drill 1.2 offset: A1 -2.5,2.5; A2 0,2.5; A3 2.5,2.5; B1 -2.5,-2.5; B2 0,-2.5; B3 2.5,-2.5

## Footprint 255-403-1000 (pad centres in mm)
Cage Clamp, Grid 10.0 mm
drill 1.2 offset: A1 -7.5,0; A2 2.5,0; A3 12.5,0; B1 -7.5,-5; B2 2.5,-5; B3 12.5,-5

## Footprint 255-403-1016 (pad centres in mm)
Cage Clamp, Grid 10.16 mm
drill 1.2 offset: A1 -7.62,0; A2 2.54,0; A3 12.7,0; B1 -7.62,-5; B2 2.54,-5; B3 12.7,-5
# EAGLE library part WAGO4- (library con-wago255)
WAGO Cage Clamp

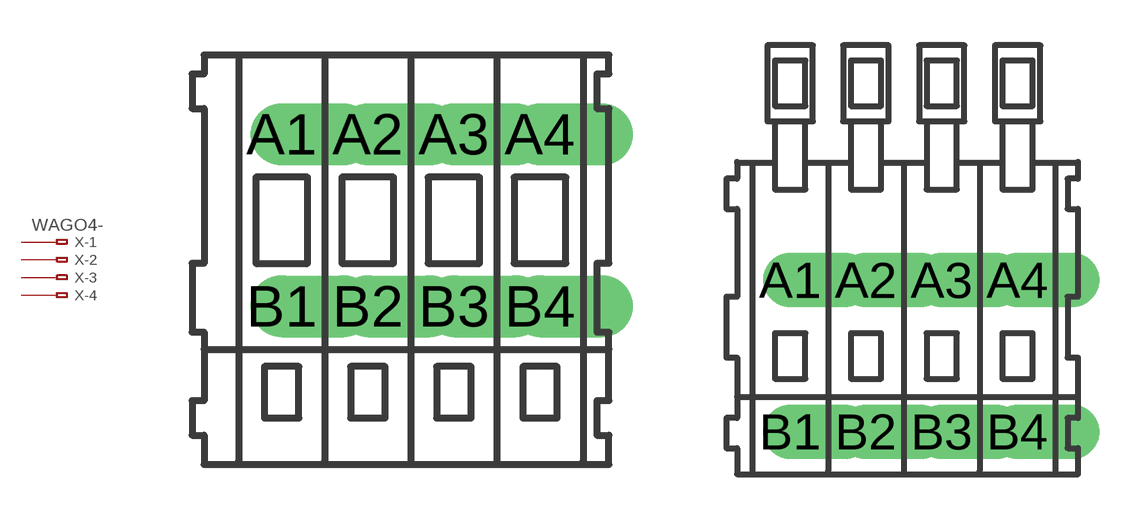
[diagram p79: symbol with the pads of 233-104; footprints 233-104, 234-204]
Designator prefix X; gates -1=KL-1V -2=KL-1 -3=KL-1 -4=KL-1

## WAGO4-233-104  [233-104]
A1  -1:A1  pas
A2  -2:A1  pas
A3  -3:A1  pas
A4  -4:A1  pas
B1  -1:B1  pas
B2  -2:B1  pas
B3  -3:B1  pas
B4  -4:B1  pas

## WAGO4-234-204  [234-204]
Pads as for 233-104

## WAGO4-255-404-1000  [255-404-1000]
Pads as for 233-104

## WAGO4-255-404-1016  [255-404-1016]
Pads as for 233-104

## WAGO4-255-404-5  [255-404-5]
Pads as for 233-104

## WAGO4-255-404-508  [255-404-508]
Pads as for 233-104

## WAGO4-255-404-750  [255-404-750]
Pads as for 233-104

## WAGO4-255-404-762  [255-404-762]
Pads as for 233-104

## Footprint 233-104 (pad centres in mm)
WAGO Cage Clamp
drill 1.2 offset: A1 -3.75,2.5; A2 -1.25,2.5; A3 1.25,2.5; A4 3.75,2.5; B1 -3.75,-2.5; B2 -1.25,-2.5; B3 1.25,-2.5; B4 3.75,-2.5

## Footprint 234-204 (pad centres in mm)
WAGO Cage Clamp
drill 1.2 offset: A1 -3.75,2.5; A2 -1.25,2.5; A3 1.25,2.5; A4 3.75,2.5; B1 -3.75,-2.5; B2 -1.25,-2.5; B3 1.25,-2.5; B4 3.75,-2.5

## Footprint 255-404-1000 (pad centres in mm)
Cage Clamp, Grid 10.0 mm
drill 1.2 offset: A1 -17.5,0; A2 -7.5,0; A3 2.5,0; A4 12.5,0; B1 -17.5,-5; B2 -7.5,-5; B3 2.5,-5; B4 12.5,-5

## Footprint 255-404-1016 (pad centres in mm)
Cage Clamp, Grid 10.16 mm
drill 1.2 offset: A1 -17.78,0; A2 -7.62,0; A3 2.54,0; A4 12.7,0; B1 -17.78,-5; B2 -7.62,-5; B3 2.54,-5; B4 12.7,-5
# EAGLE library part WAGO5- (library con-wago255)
WAGO Cage Clamp

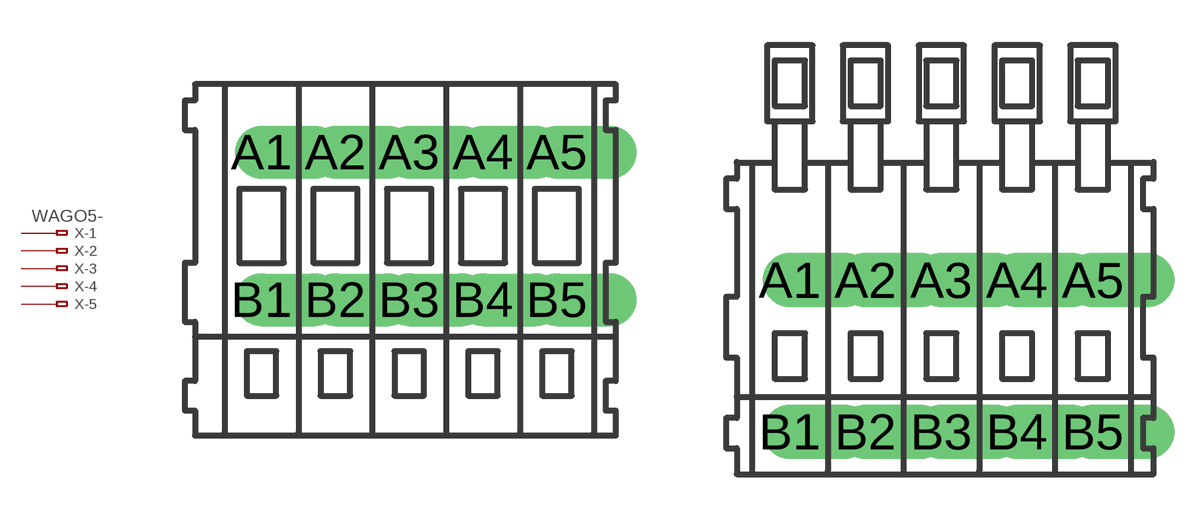
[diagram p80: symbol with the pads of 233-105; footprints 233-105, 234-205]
Designator prefix X; gates -1=KL-1V -2=KL-1 -3=KL-1 -4=KL-1 -5=KL-1

## WAGO5-233-105  [233-105]
A1  -1:A1  pas
A2  -2:A1  pas
A3  -3:A1  pas
A4  -4:A1  pas
A5  -5:A1  pas
B1  -1:B1  pas
B2  -2:B1  pas
B3  -3:B1  pas
B4  -4:B1  pas
B5  -5:B1  pas

## WAGO5-234-205  [234-205]
Pads as for 233-105

## WAGO5-255-405-1000  [255-405-1000]
Pads as for 233-105

## WAGO5-255-405-1016  [255-405-1016]
Pads as for 233-105

## WAGO5-255-405-5  [255-405-5]
Pads as for 233-105

## WAGO5-255-405-508  [255-405-508]
Pads as for 233-105

## WAGO5-255-405-750  [255-405-750]
Pads as for 233-105

## WAGO5-255-405-762  [255-405-762]
Pads as for 233-105

## Footprint 233-105 (pad centres in mm)
WAGO Cage Clamp
drill 1.2 offset: A1 -5,2.5; A2 -2.5,2.5; A3 0,2.5; A4 2.5,2.5; A5 5,2.5; B1 -5,-2.5; B2 -2.5,-2.5; B3 0,-2.5; B4 2.5,-2.5; B5 5,-2.5

## Footprint 234-205 (pad centres in mm)
WAGO Cage Clamp
drill 1.2 offset: A1 -5,2.5; A2 -2.5,2.5; A3 0,2.5; A4 2.5,2.5; A5 5,2.5; B1 -5,-2.5; B2 -2.5,-2.5; B3 0,-2.5; B4 2.5,-2.5; B5 5,-2.5

## Footprint 255-405-1000 (pad centres in mm)
Cage Clamp, Grid 10.0 mm
drill 1.2 offset: A1 -17.5,0; A2 -7.5,0; A3 2.5,0; A4 12.5,0; A5 22.5,0; B1 -17.5,-5; B2 -7.5,-5; B3 2.5,-5; B4 12.5,-5; B5 22.5,-5

## Footprint 255-405-1016 (pad centres in mm)
Cage Clamp, Grid 10.16 mm
drill 1.2 offset: A1 -17.78,0; A2 -7.62,0; A3 2.54,0; A4 12.7,0; A5 22.86,0; B1 -17.78,-5; B2 -7.62,-5; B3 2.54,-5; B4 12.7,-5; B5 22.86,-5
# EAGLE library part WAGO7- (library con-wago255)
WAGO Cage Clamp

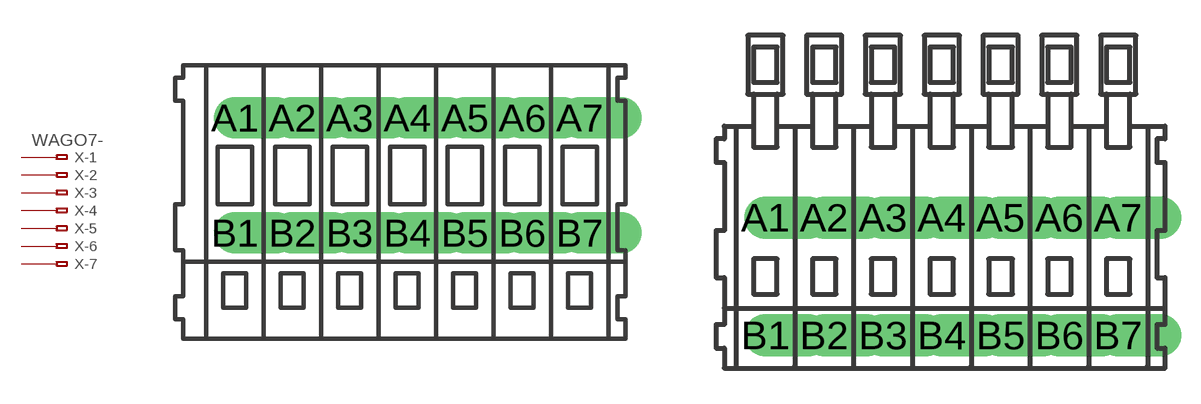
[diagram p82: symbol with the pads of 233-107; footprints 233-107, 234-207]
Designator prefix X; gates -1=KL-1V -2=KL-1 -3=KL-1 -4=KL-1 -5=KL-1 -6=KL-1 -7=KL-1

## WAGO7-233-107  [233-107]
A1  -1:A1  pas
A2  -2:A1  pas
A3  -3:A1  pas
A4  -4:A1  pas
A5  -5:A1  pas
A6  -6:A1  pas
A7  -7:A1  pas
B1  -1:B1  pas
B2  -2:B1  pas
B3  -3:B1  pas
B4  -4:B1  pas
B5  -5:B1  pas
B6  -6:B1  pas
B7  -7:B1  pas

## WAGO7-234-207  [234-207]
Pads as for 233-107

## WAGO7-255-407-1000  [255-407-1000]
Pads as for 233-107

## WAGO7-255-407-1016  [255-407-1016]
Pads as for 233-107

## WAGO7-255-407-5  [255-407-5]
Pads as for 233-107

## WAGO7-255-407-508  [255-407-508]
Pads as for 233-107

## WAGO7-255-407-750  [255-407-750]
Pads as for 233-107

## WAGO7-255-407-762  [255-407-762]
Pads as for 233-107

## Footprint 233-107 (pad centres in mm)
WAGO Cage Clamp
drill 1.2 offset: A1 -7.5,2.5; A2 -5,2.5; A3 -2.5,2.5; A4 0,2.5; A5 2.5,2.5; A6 5,2.5; A7 7.5,2.5; B1 -7.5,-2.5; B2 -5,-2.5; B3 -2.5,-2.5; B4 0,-2.5; B5 2.5,-2.5; B6 5,-2.5; B7 7.5,-2.5

## Footprint 234-207 (pad centres in mm)
WAGO Cage Clamp
drill 1.2 offset: A1 -7.5,2.5; A2 -5,2.5; A3 -2.5,2.5; A4 0,2.5; A5 2.5,2.5; A6 5,2.5; A7 7.5,2.5; B1 -7.5,-2.5; B2 -5,-2.5; B3 -2.5,-2.5; B4 0,-2.5; B5 2.5,-2.5; B6 5,-2.5; B7 7.5,-2.5

## Footprint 255-407-1000 (pad centres in mm)
Cage Clamp, Grid 10.0 mm
drill 1.2 offset: A1 -27.5,0; A2 -17.5,0; A3 -7.5,0; A4 2.5,0; A5 12.5,0; A6 22.5,0; A7 32.5,0; B1 -27.5,-5; B2 -17.5,-5; B3 -7.5,-5; B4 2.5,-5; B5 12.5,-5; B6 22.5,-5; B7 32.5,-5

## Footprint 255-407-1016 (pad centres in mm)
Cage Clamp, Grid 10.16 mm
drill 1.2 offset: A1 -27.94,0; A2 -17.78,0; A3 -7.62,0; A4 2.54,0; A5 12.7,0; A6 22.86,0; A7 33.02,0; B1 -27.94,-5; B2 -17.78,-5; B3 -7.62,-5; B4 2.54,-5; B5 12.7,-5; B6 22.86,-5; B7 33.02,-5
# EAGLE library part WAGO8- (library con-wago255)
WAGO Cage Clamp

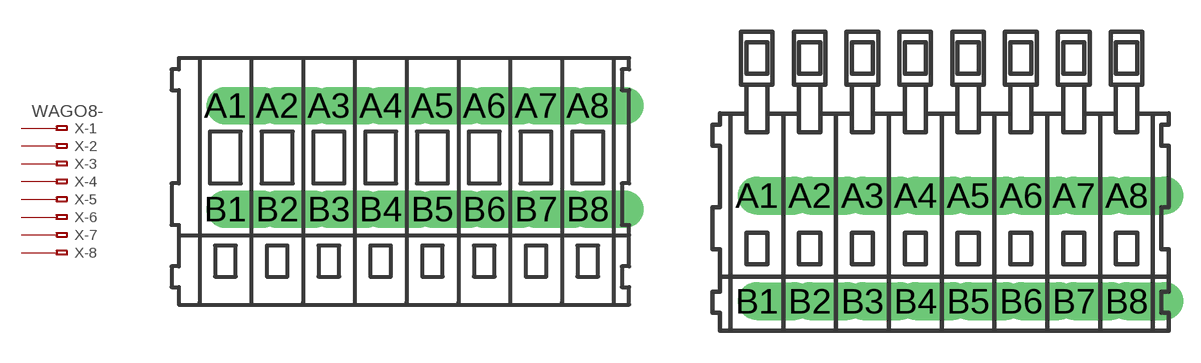
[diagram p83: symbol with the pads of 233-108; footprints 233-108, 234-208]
Designator prefix X; gates -1=KL-1V -2=KL-1 -3=KL-1 -4=KL-1 -5=KL-1 -6=KL-1 -7=KL-1 -8=KL-1

## WAGO8-233-108  [233-108]
A1  -1:A1  pas
A2  -2:A1  pas
A3  -3:A1  pas
A4  -4:A1  pas
A5  -5:A1  pas
A6  -6:A1  pas
A7  -7:A1  pas
A8  -8:A1  pas
B1  -1:B1  pas
B2  -2:B1  pas
B3  -3:B1  pas
B4  -4:B1  pas
B5  -5:B1  pas
B6  -6:B1  pas
B7  -7:B1  pas
B8  -8:B1  pas

## WAGO8-234-208  [234-208]
Pads as for 233-108

## WAGO8-255-408-1000  [255-408-1000]
Pads as for 233-108

## WAGO8-255-408-1016  [255-408-1016]
Pads as for 233-108

## WAGO8-255-408-5  [255-408-5]
Pads as for 233-108

## WAGO8-255-408-508  [255-408-508]
Pads as for 233-108

## WAGO8-255-408-750  [255-408-750]
Pads as for 233-108

## WAGO8-255-408-762  [255-408-762]
Pads as for 233-108

## Footprint 233-108 (pad centres in mm)
WAGO Cage Clamp
drill 1.2 offset: A1 -8.75,2.5; A2 -6.25,2.5; A3 -3.75,2.5; A4 -1.25,2.5; A5 1.25,2.5; A6 3.75,2.5; A7 6.25,2.5; A8 8.75,2.5; B1 -8.75,-2.5; B2 -6.25,-2.5; B3 -3.75,-2.5; B4 -1.25,-2.5; B5 1.25,-2.5; B6 3.75,-2.5; B7 6.25,-2.5; B8 8.75,-2.5

## Footprint 234-208 (pad centres in mm)
WAGO Cage Clamp
drill 1.2 offset: A1 -8.75,2.5; A2 -6.25,2.5; A3 -3.75,2.5; A4 -1.25,2.5; A5 1.25,2.5; A6 3.75,2.5; A7 6.25,2.5; A8 8.75,2.5; B1 -8.75,-2.5; B2 -6.25,-2.5; B3 -3.75,-2.5; B4 -1.25,-2.5; B5 1.25,-2.5; B6 3.75,-2.5; B7 6.25,-2.5; B8 8.75,-2.5

## Footprint 255-408-1000 (pad centres in mm)
Cage Clamp, Grid 10.0 mm
drill 1.2 offset: A1 -37.5,0; A2 -27.5,0; A3 -17.5,0; A4 -7.5,0; A5 2.5,0; A6 12.5,0; A7 22.5,0; A8 32.5,0; B1 -37.5,-5; B2 -27.5,-5; B3 -17.5,-5; B4 -7.5,-5; B5 2.5,-5; B6 12.5,-5; B7 22.5,-5; B8 32.5,-5

## Footprint 255-408-1016 (pad centres in mm)
Cage Clamp, Grid 10.16 mm
drill 1.2 offset: A1 -38.1,0; A2 -27.94,0; A3 -17.78,0; A4 -7.62,0; A5 2.54,0; A6 12.7,0; A7 22.86,0; A8 33.02,0; B1 -38.1,-5; B2 -27.94,-5; B3 -17.78,-5; B4 -7.62,-5; B5 2.54,-5; B6 12.7,-5; B7 22.86,-5; B8 33.02,-5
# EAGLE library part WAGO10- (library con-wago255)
WAGO Cage Clamp

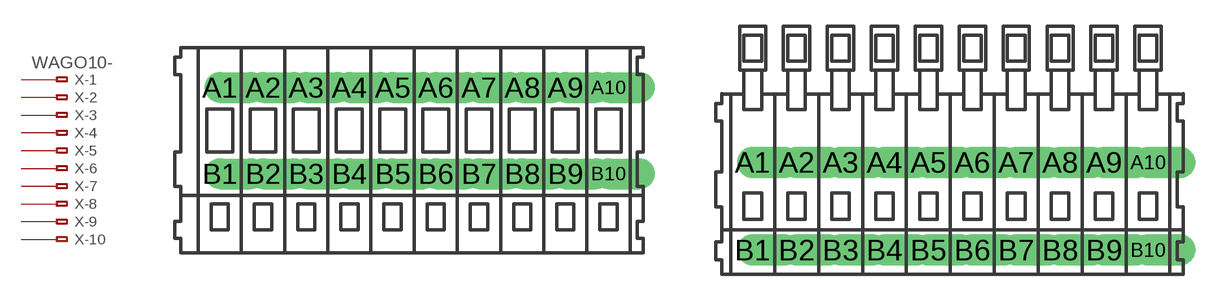
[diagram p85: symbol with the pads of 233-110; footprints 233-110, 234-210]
Designator prefix X; gates -1=KL-1V -2=KL-1 -3=KL-1 -4=KL-1 -5=KL-1 -6=KL-1 -7=KL-1 -8=KL-1 -9=KL-1 -10=KL-1

## WAGO10-233-110  [233-110]
A1  -1:A1  pas
A2  -2:A1  pas
A3  -3:A1  pas
A4  -4:A1  pas
A5  -5:A1  pas
A6  -6:A1  pas
A7  -7:A1  pas
A8  -8:A1  pas
A9  -9:A1  pas
A10  -10:A1  pas
B1  -1:B1  pas
B2  -2:B1  pas
B3  -3:B1  pas
B4  -4:B1  pas
B5  -5:B1  pas
B6  -6:B1  pas
B7  -7:B1  pas
B8  -8:B1  pas
B9  -9:B1  pas
B10  -10:B1  pas

## WAGO10-234-210  [234-210]
Pads as for 233-110

## WAGO10-255-410-1000  [255-410-1000]
Pads as for 233-110

## WAGO10-255-410-1016  [255-410-1016]
Pads as for 233-110

## WAGO10-255-410-5  [255-410-5]
Pads as for 233-110

## WAGO10-255-410-508  [255-410-508]
Pads as for 233-110

## WAGO10-255-410-750  [255-410-750]
Pads as for 233-110

## WAGO10-255-410-762  [255-410-762]
Pads as for 233-110

## Footprint 233-110 (pad centres in mm)
WAGO Cage Clamp
drill 1.2 offset: A1 -11.25,2.5; A2 -8.75,2.5; A3 -6.25,2.5; A4 -3.75,2.5; A5 -1.25,2.5; A6 1.25,2.5; A7 3.75,2.5; A8 6.25,2.5; A9 8.75,2.5; A10 11.25,2.5; B1 -11.25,-2.5; B2 -8.75,-2.5; B3 -6.25,-2.5; B4 -3.75,-2.5; B5 -1.25,-2.5; B6 1.25,-2.5; B7 3.75,-2.5; B8 6.25,-2.5; B9 8.75,-2.5; B10 11.25,-2.5

## Footprint 234-210 (pad centres in mm)
WAGO Cage Clamp
drill 1.2 offset: A1 -11.25,2.5; A2 -8.75,2.5; A3 -6.25,2.5; A4 -3.75,2.5; A5 -1.25,2.5; A6 1.25,2.5; A7 3.75,2.5; A8 6.25,2.5; A9 8.75,2.5; A10 11.25,2.5; B1 -11.25,-2.5; B2 -8.75,-2.5; B3 -6.25,-2.5; B4 -3.75,-2.5; B5 -1.25,-2.5; B6 1.25,-2.5; B7 3.75,-2.5; B8 6.25,-2.5; B9 8.75,-2.5; B10 11.25,-2.5

## Footprint 255-410-1000 (pad centres in mm)
Cage Clamp, Grid 10.0 mm
drill 1.2 offset: A1 -47.5,0; A2 -37.5,0; A3 -27.5,0; A4 -17.5,0; A5 -7.5,0; A6 2.5,0; A7 12.5,0; A8 22.5,0; A9 32.5,0; A10 42.5,0; B1 -47.5,-5; B2 -37.5,-5; B3 -27.5,-5; B4 -17.5,-5; B5 -7.5,-5; B6 2.5,-5; B7 12.5,-5; B8 22.5,-5; B9 32.5,-5; B10 42.5,-5

## Footprint 255-410-1016 (pad centres in mm)
Cage Clamp, Grid 10.16 mm
drill 1.2 offset: A1 -48.26,0; A2 -38.1,0; A3 -27.94,0; A4 -17.78,0; A5 -7.62,0; A6 2.54,0; A7 12.7,0; A8 22.86,0; A9 33.02,0; A10 43.18,0; B1 -48.26,-5; B2 -38.1,-5; B3 -27.94,-5; B4 -17.78,-5; B5 -7.62,-5; B6 2.54,-5; B7 12.7,-5; B8 22.86,-5; B9 33.02,-5; B10 43.18,-5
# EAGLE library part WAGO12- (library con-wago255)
WAGO Cage Clamp

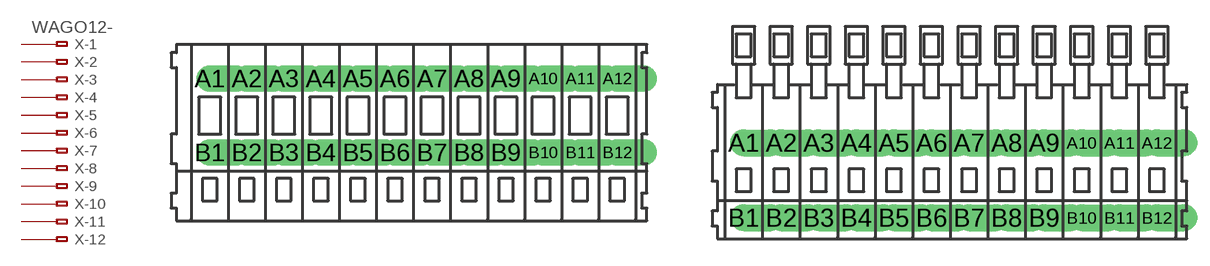
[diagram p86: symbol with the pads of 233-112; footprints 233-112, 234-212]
Designator prefix X; gates -1=KL-1V -2=KL-1 -3=KL-1 -4=KL-1 -5=KL-1 -6=KL-1 -7=KL-1 -8=KL-1 -9=KL-1 -10=KL-1 -11=KL-1 -12=KL-1

## WAGO12-233-112  [233-112]
A1  -1:A1  pas
A2  -2:A1  pas
A3  -3:A1  pas
A4  -4:A1  pas
A5  -5:A1  pas
A6  -6:A1  pas
A7  -7:A1  pas
A8  -8:A1  pas
A9  -9:A1  pas
A10  -10:A1  pas
A11  -11:A1  pas
A12  -12:A1  pas
B1  -1:B1  pas
B2  -2:B1  pas
B3  -3:B1  pas
B4  -4:B1  pas
B5  -5:B1  pas
B6  -6:B1  pas
B7  -7:B1  pas
B8  -8:B1  pas
B9  -9:B1  pas
B10  -10:B1  pas
B11  -11:B1  pas
B12  -12:B1  pas

## WAGO12-234-212  [234-212]
Pads as for 233-112

## WAGO12-255-412-1000  [255-412-1000]
Pads as for 233-112

## WAGO12-255-412-1016  [255-412-1016]
Pads as for 233-112

## WAGO12-255-412-5  [255-412-5]
Pads as for 233-112

## WAGO12-255-412-508  [255-412-508]
Pads as for 233-112

## WAGO12-255-412-750  [255-412-750]
Pads as for 233-112

## WAGO12-255-412-762  [255-412-762]
Pads as for 233-112

## Footprint 233-112 (pad centres in mm)
WAGO Cage Clamp
drill 1.2 offset: A1 -13.75,2.5; A2 -11.25,2.5; A3 -8.75,2.5; A4 -6.25,2.5; A5 -3.75,2.5; A6 -1.25,2.5; A7 1.25,2.5; A8 3.75,2.5; A9 6.25,2.5; A10 8.75,2.5; A11 11.25,2.5; A12 13.75,2.5; B1 -13.75,-2.5; B2 -11.25,-2.5; B3 -8.75,-2.5; B4 -6.25,-2.5; B5 -3.75,-2.5; B6 -1.25,-2.5; B7 1.25,-2.5; B8 3.75,-2.5; B9 6.25,-2.5; B10 8.75,-2.5; B11 11.25,-2.5; B12 13.75,-2.5

## Footprint 234-212 (pad centres in mm)
WAGO Cage Clamp
drill 1.2 offset: A1 -13.75,2.5; A2 -11.25,2.5; A3 -8.75,2.5; A4 -6.25,2.5; A5 -3.75,2.5; A6 -1.25,2.5; A7 1.25,2.5; A8 3.75,2.5; A9 6.25,2.5; A10 8.75,2.5; A11 11.25,2.5; A12 13.75,2.5; B1 -13.75,-2.5; B2 -11.25,-2.5; B3 -8.75,-2.5; B4 -6.25,-2.5; B5 -3.75,-2.5; B6 -1.25,-2.5; B7 1.25,-2.5; B8 3.75,-2.5; B9 6.25,-2.5; B10 8.75,-2.5; B11 11.25,-2.5; B12 13.75,-2.5

## Footprint 255-412-1000 (pad centres in mm)
Cage Clamp, Grid 10.0 mm
drill 1.2 offset: A1 -57.5,0; A2 -47.5,0; A3 -37.5,0; A4 -27.5,0; A5 -17.5,0; A6 -7.5,0; A7 2.5,0; A8 12.5,0; A9 22.5,0; A10 32.5,0; A11 42.5,0; A12 52.5,0; B1 -57.5,-5; B2 -47.5,-5; B3 -37.5,-5; B4 -27.5,-5; B5 -17.5,-5; B6 -7.5,-5; B7 2.5,-5; B8 12.5,-5; B9 22.5,-5; B10 32.5,-5; B11 42.5,-5; B12 52.5,-5

## Footprint 255-412-1016 (pad centres in mm)
Cage Clamp, Grid 10.16 mm
drill 1.2 offset: A1 -58.42,0; A2 -48.26,0; A3 -38.1,0; A4 -27.94,0; A5 -17.78,0; A6 -7.62,0; A7 2.54,0; A8 12.7,0; A9 22.86,0; A10 33.02,0; A11 43.18,0; A12 53.34,0; B1 -58.42,-5; B2 -48.26,-5; B3 -38.1,-5; B4 -27.94,-5; B5 -17.78,-5; B6 -7.62,-5; B7 2.54,-5; B8 12.7,-5; B9 22.86,-5; B10 33.02,-5; B11 43.18,-5; B12 53.34,-5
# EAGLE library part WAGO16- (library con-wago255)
WAGO Cage Clamp

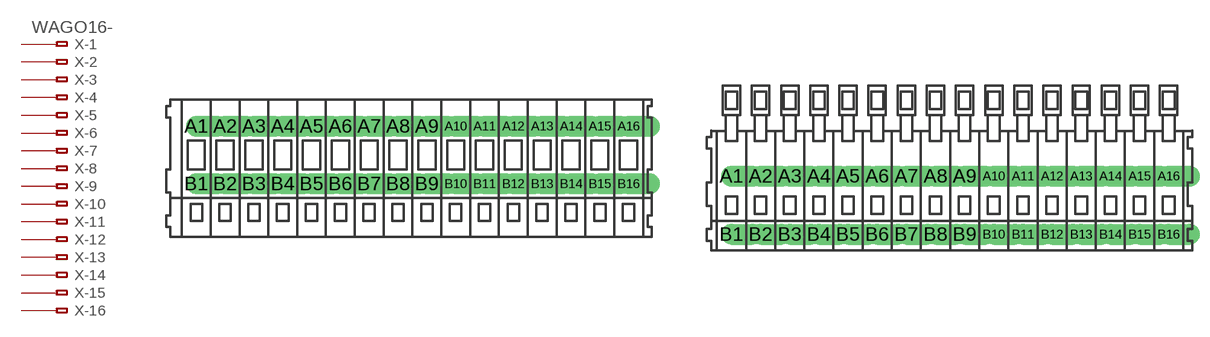
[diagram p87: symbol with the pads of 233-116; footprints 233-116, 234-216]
Designator prefix X; gates -1=KL-1V -2=KL-1 -3=KL-1 -4=KL-1 -5=KL-1 -6=KL-1 -7=KL-1 -8=KL-1 -9=KL-1 -10=KL-1 -11=KL-1 -12=KL-1 -13=KL-1 -14=KL-1 -15=KL-1 -16=KL-1

## WAGO16-233-116  [233-116]
A1  -1:A1  pas
A2  -2:A1  pas
A3  -3:A1  pas
A4  -4:A1  pas
A5  -5:A1  pas
A6  -6:A1  pas
A7  -7:A1  pas
A8  -8:A1  pas
A9  -9:A1  pas
A10  -10:A1  pas
A11  -11:A1  pas
A12  -12:A1  pas
A13  -13:A1  pas
A14  -14:A1  pas
A15  -15:A1  pas
A16  -16:A1  pas
B1  -1:B1  pas
B2  -2:B1  pas
B3  -3:B1  pas
B4  -4:B1  pas
B5  -5:B1  pas
B6  -6:B1  pas
B7  -7:B1  pas
B8  -8:B1  pas
B9  -9:B1  pas
B10  -10:B1  pas
B11  -11:B1  pas
B12  -12:B1  pas
B13  -13:B1  pas
B14  -14:B1  pas
B15  -15:B1  pas
B16  -16:B1  pas

## WAGO16-234-216  [234-216]
Pads as for 233-116

## WAGO16-255-416-1000  [255-416-1000]
Pads as for 233-116

## WAGO16-255-416-1016  [255-416-1016]
Pads as for 233-116

## WAGO16-255-416-5  [255-416-5]
Pads as for 233-116

## WAGO16-255-416-508  [255-416-508]
Pads as for 233-116

## WAGO16-255-416-750  [255-416-750]
Pads as for 233-116

## WAGO16-255-416-762  [255-416-762]
Pads as for 233-116

## Footprint 233-116 (pad centres in mm)
WAGO Cage Clamp
drill 1.2 offset: A1 -18.75,2.5; A2 -16.25,2.5; A3 -13.75,2.5; A4 -11.25,2.5; A5 -8.75,2.5; A6 -6.25,2.5; A7 -3.75,2.5; A8 -1.25,2.5; A9 1.25,2.5; A10 3.75,2.5; A11 6.25,2.5; A12 8.75,2.5; A13 11.25,2.5; A14 13.75,2.5; A15 16.25,2.5; A16 18.75,2.5; B1 -18.75,-2.5; B2 -16.25,-2.5; B3 -13.75,-2.5; B4 -11.25,-2.5; B5 -8.75,-2.5; B6 -6.25,-2.5; B7 -3.75,-2.5; B8 -1.25,-2.5; B9 1.25,-2.5; B10 3.75,-2.5; B11 6.25,-2.5; B12 8.75,-2.5; B13 11.25,-2.5; B14 13.75,-2.5; B15 16.25,-2.5; B16 18.75,-2.5

## Footprint 234-216 (pad centres in mm)
WAGO Cage Clamp
drill 1.2 offset: A1 -18.75,2.5; A2 -16.25,2.5; A3 -13.75,2.5; A4 -11.25,2.5; A5 -8.75,2.5; A6 -6.25,2.5; A7 -3.75,2.5; A8 -1.25,2.5; A9 1.25,2.5; A10 3.75,2.5; A11 6.25,2.5; A12 8.75,2.5; A13 11.25,2.5; A14 13.75,2.5; A15 16.25,2.5; A16 18.75,2.5; B1 -18.75,-2.5; B2 -16.25,-2.5; B3 -13.75,-2.5; B4 -11.25,-2.5; B5 -8.75,-2.5; B6 -6.25,-2.5; B7 -3.75,-2.5; B8 -1.25,-2.5; B9 1.25,-2.5; B10 3.75,-2.5; B11 6.25,-2.5; B12 8.75,-2.5; B13 11.25,-2.5; B14 13.75,-2.5; B15 16.25,-2.5; B16 18.75,-2.5

## Footprint 255-416-1000 (pad centres in mm)
Cage Clamp, Grid 10.0 mm
drill 1.2 offset: A1 -77.5,0; A2 -67.5,0; A3 -57.5,0; A4 -47.5,0; A5 -37.5,0; A6 -27.5,0; A7 -17.5,0; A8 -7.5,0; A9 2.5,0; A10 12.5,0; A11 22.5,0; A12 32.5,0; A13 42.5,0; A14 52.5,0; A15 62.5,0; A16 72.5,0; B1 -77.5,-5; B2 -67.5,-5; B3 -57.5,-5; B4 -47.5,-5; B5 -37.5,-5; B6 -27.5,-5; B7 -17.5,-5; B8 -7.5,-5; B9 2.5,-5; B10 12.5,-5; B11 22.5,-5; B12 32.5,-5; B13 42.5,-5; B14 52.5,-5; B15 62.5,-5; B16 72.5,-5

## Footprint 255-416-1016 (pad centres in mm)
Cage Clamp, Grid 10.16 mm
drill 1.2 offset: A1 -78.74,0; A2 -68.58,0; A3 -58.42,0; A4 -48.26,0; A5 -38.1,0; A6 -27.94,0; A7 -17.78,0; A8 -7.62,0; A9 2.54,0; A10 12.7,0; A11 22.86,0; A12 33.02,0; A13 43.18,0; A14 53.34,0; A15 63.5,0; A16 73.66,0; B1 -78.74,-5; B2 -68.58,-5; B3 -58.42,-5; B4 -48.26,-5; B5 -38.1,-5; B6 -27.94,-5; B7 -17.78,-5; B8 -7.62,-5; B9 2.54,-5; B10 12.7,-5; B11 22.86,-5; B12 33.02,-5; B13 43.18,-5; B14 53.34,-5; B15 63.5,-5; B16 73.66,-5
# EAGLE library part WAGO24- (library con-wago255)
WAGO Cage Clamp

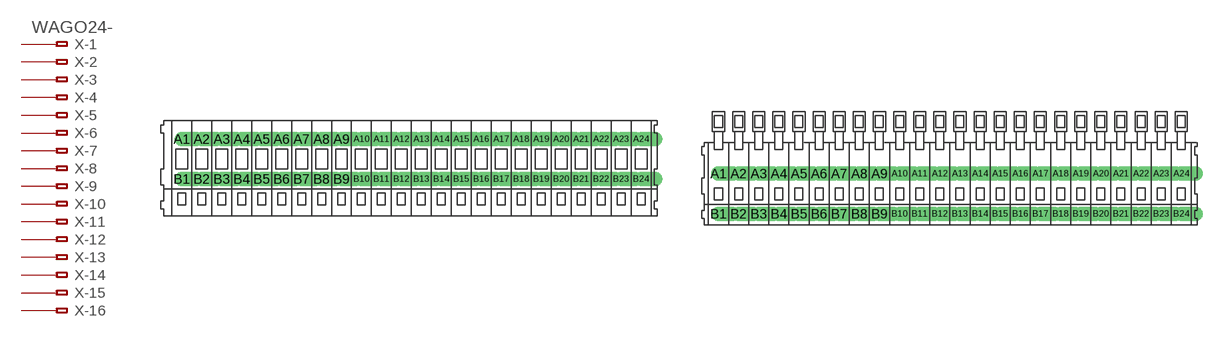
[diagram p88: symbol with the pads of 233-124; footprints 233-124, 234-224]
Designator prefix X; gates -1=KL-1V -2=KL-1 -3=KL-1 -4=KL-1 -5=KL-1 -6=KL-1 -7=KL-1 -8=KL-1 -9=KL-1 -10=KL-1 -11=KL-1 -12=KL-1 -13=KL-1 -14=KL-1 -15=KL-1 -16=KL-1 -17=KL-1 -18=KL-1 -19=KL-1 -20=KL-1 -21=KL-1 -22=KL-1 -23=KL-1 -24=KL-1

## WAGO24-233-124  [233-124]
A1  -1:A1  pas
A2  -2:A1  pas
A3  -3:A1  pas
A4  -4:A1  pas
A5  -5:A1  pas
A6  -6:A1  pas
A7  -7:A1  pas
A8  -8:A1  pas
A9  -9:A1  pas
A10  -10:A1  pas
A11  -11:A1  pas
A12  -12:A1  pas
A13  -13:A1  pas
A14  -14:A1  pas
A15  -15:A1  pas
A16  -16:A1  pas
A17  -17:A1  pas
A18  -18:A1  pas
A19  -19:A1  pas
A20  -20:A1  pas
A21  -21:A1  pas
A22  -22:A1  pas
A23  -23:A1  pas
A24  -24:A1  pas
B1  -1:B1  pas
B2  -2:B1  pas
B3  -3:B1  pas
B4  -4:B1  pas
B5  -5:B1  pas
B6  -6:B1  pas
B7  -7:B1  pas
B8  -8:B1  pas
B9  -9:B1  pas
B10  -10:B1  pas
B11  -11:B1  pas
B12  -12:B1  pas
B13  -13:B1  pas
B14  -14:B1  pas
B15  -15:B1  pas
B16  -16:B1  pas
B17  -17:B1  pas
B18  -18:B1  pas
B19  -19:B1  pas
B20  -20:B1  pas
B21  -21:B1  pas
B22  -22:B1  pas
B23  -23:B1  pas
B24  -24:B1  pas

## WAGO24-234-224  [234-224]
Pads as for 233-124

## WAGO24-255-424-1000  [255-424-1000]
Pads as for 233-124

## WAGO24-255-424-1016  [255-424-1016]
Pads as for 233-124

## WAGO24-255-424-5  [255-424-5]
Pads as for 233-124

## WAGO24-255-424-508  [255-424-508]
Pads as for 233-124

## WAGO24-255-424-750  [255-424-750]
Pads as for 233-124

## WAGO24-255-424-762  [255-424-762]
Pads as for 233-124

## Footprint 233-124 (pad centres in mm)
WAGO Cage Clamp
drill 1.2 offset: A1 -28.75,2.5; A2 -26.25,2.5; A3 -23.75,2.5; A4 -21.25,2.5; A5 -18.75,2.5; A6 -16.25,2.5; A7 -13.75,2.5; A8 -11.25,2.5; A9 -8.75,2.5; A10 -6.25,2.5; A11 -3.75,2.5; A12 -1.25,2.5; A13 1.25,2.5; A14 3.75,2.5; A15 6.25,2.5; A16 8.75,2.5; A17 11.25,2.5; A18 13.75,2.5; A19 16.25,2.5; A20 18.75,2.5; A21 21.25,2.5; A22 23.75,2.5; A23 26.25,2.5; A24 28.75,2.5; B1 -28.75,-2.5; B2 -26.25,-2.5; B3 -23.75,-2.5; B4 -21.25,-2.5; B5 -18.75,-2.5; B6 -16.25,-2.5; B7 -13.75,-2.5; B8 -11.25,-2.5; B9 -8.75,-2.5; B10 -6.25,-2.5; B11 -3.75,-2.5; B12 -1.25,-2.5; B13 1.25,-2.5; B14 3.75,-2.5; B15 6.25,-2.5; B16 8.75,-2.5; B17 11.25,-2.5; B18 13.75,-2.5; B19 16.25,-2.5; B20 18.75,-2.5; B21 21.25,-2.5; B22 23.75,-2.5; B23 26.25,-2.5; B24 28.75,-2.5

## Footprint 234-224 (pad centres in mm)
WAGO Cage Clamp
drill 1.2 offset: A1 -28.75,2.5; A2 -26.25,2.5; A3 -23.75,2.5; A4 -21.25,2.5; A5 -18.75,2.5; A6 -16.25,2.5; A7 -13.75,2.5; A8 -11.25,2.5; A9 -8.75,2.5; A10 -6.25,2.5; A11 -3.75,2.5; A12 -1.25,2.5; A13 1.25,2.5; A14 3.75,2.5; A15 6.25,2.5; A16 8.75,2.5; A17 11.25,2.5; A18 13.75,2.5; A19 16.25,2.5; A20 18.75,2.5; A21 21.25,2.5; A22 23.75,2.5; A23 26.25,2.5; A24 28.75,2.5; B1 -28.75,-2.5; B2 -26.25,-2.5; B3 -23.75,-2.5; B4 -21.25,-2.5; B5 -18.75,-2.5; B6 -16.25,-2.5; B7 -13.75,-2.5; B8 -11.25,-2.5; B9 -8.75,-2.5; B10 -6.25,-2.5; B11 -3.75,-2.5; B12 -1.25,-2.5; B13 1.25,-2.5; B14 3.75,-2.5; B15 6.25,-2.5; B16 8.75,-2.5; B17 11.25,-2.5; B18 13.75,-2.5; B19 16.25,-2.5; B20 18.75,-2.5; B21 21.25,-2.5; B22 23.75,-2.5; B23 26.25,-2.5; B24 28.75,-2.5

## Footprint 255-424-1000 (pad centres in mm)
Cage Clamp, Grid 10.0 mm
drill 1.2 offset: A1 -117.5,0; A2 -107.5,0; A3 -97.5,0; A4 -87.5,0; A5 -77.5,0; A6 -67.5,0; A7 -57.5,0; A8 -47.5,0; A9 -37.5,0; A10 -27.5,0; A11 -17.5,0; A12 -7.5,0; A13 2.5,0; A14 12.5,0; A15 22.5,0; A16 32.5,0; A17 42.5,0; A18 52.5,0; A19 62.5,0; A20 72.5,0; A21 82.5,0; A22 92.5,0; A23 102.5,0; A24 112.5,0; B1 -117.5,-5; B2 -107.5,-5; B3 -97.5,-5; B4 -87.5,-5; B5 -77.5,-5; B6 -67.5,-5; B7 -57.5,-5; B8 -47.5,-5; B9 -37.5,-5; B10 -27.5,-5; B11 -17.5,-5; B12 -7.5,-5; B13 2.5,-5; B14 12.5,-5; B15 22.5,-5; B16 32.5,-5; B17 42.5,-5; B18 52.5,-5; B19 62.5,-5; B20 72.5,-5; B21 82.5,-5; B22 92.5,-5; B23 102.5,-5; B24 112.5,-5

## Footprint 255-424-1016 (pad centres in mm)
Cage Clamp, Grid 10.16 mm
drill 1.2 offset: A1 -119.38,0; A2 -109.22,0; A3 -99.06,0; A4 -88.9,0; A5 -78.74,0; A6 -68.58,0; A7 -58.42,0; A8 -48.26,0; A9 -38.1,0; A10 -27.94,0; A11 -17.78,0; A12 -7.62,0; A13 2.54,0; A14 12.7,0; A15 22.86,0; A16 33.02,0; A17 43.18,0; A18 53.34,0; A19 63.5,0; A20 73.66,0; A21 83.82,0; A22 93.98,0; A23 104.14,0; A24 114.3,0; B1 -119.38,-5; B2 -109.22,-5; B3 -99.06,-5; B4 -88.9,-5; B5 -78.74,-5; B6 -68.58,-5; B7 -58.42,-5; B8 -48.26,-5; B9 -38.1,-5; B10 -27.94,-5; B11 -17.78,-5; B12 -7.62,-5; B13 2.54,-5; B14 12.7,-5; B15 22.86,-5; B16 33.02,-5; B17 43.18,-5; B18 53.34,-5; B19 63.5,-5; B20 73.66,-5; B21 83.82,-5; B22 93.98,-5; B23 104.14,-5; B24 114.3,-5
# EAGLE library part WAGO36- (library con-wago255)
WAGO Cage Clamp

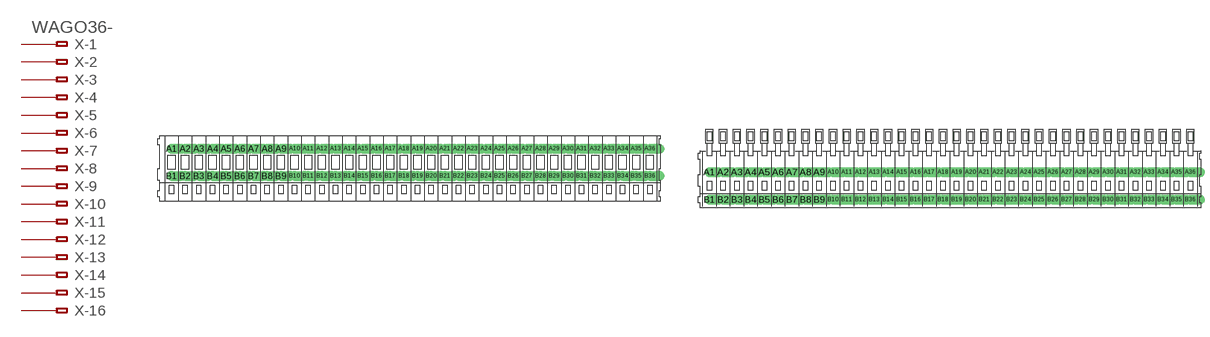
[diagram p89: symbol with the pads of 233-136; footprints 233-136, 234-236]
Designator prefix X; gates -1=KL-1V -2=KL-1 -3=KL-1 -4=KL-1 -5=KL-1 -6=KL-1 -7=KL-1 -8=KL-1 -9=KL-1 -10=KL-1 -11=KL-1 -12=KL-1 -13=KL-1 -14=KL-1 -15=KL-1 -16=KL-1 -17=KL-1 -18=KL-1 -19=KL-1 -20=KL-1 -21=KL-1 -22=KL-1 -23=KL-1 -24=KL-1 -25=KL-1 -26=KL-1 -27=KL-1 -28=KL-1 -29=KL-1 -30=KL-1 -31=KL-1 -32=KL-1 -33=KL-1 -34=KL-1 -35=KL-1 -36=KL-1

## WAGO36-233-136  [233-136]
A1  -1:A1  pas
A2  -2:A1  pas
A3  -3:A1  pas
A4  -4:A1  pas
A5  -5:A1  pas
A6  -6:A1  pas
A7  -7:A1  pas
A8  -8:A1  pas
A9  -9:A1  pas
A10  -10:A1  pas
A11  -11:A1  pas
A12  -12:A1  pas
A13  -13:A1  pas
A14  -14:A1  pas
A15  -15:A1  pas
A16  -16:A1  pas
A17  -17:A1  pas
A18  -18:A1  pas
A19  -19:A1  pas
A20  -20:A1  pas
A21  -21:A1  pas
A22  -22:A1  pas
A23  -23:A1  pas
A24  -24:A1  pas
A25  -25:A1  pas
A26  -26:A1  pas
A27  -27:A1  pas
A28  -28:A1  pas
A29  -29:A1  pas
A30  -30:A1  pas
A31  -31:A1  pas
A32  -32:A1  pas
A33  -33:A1  pas
A34  -34:A1  pas
A35  -35:A1  pas
A36  -36:A1  pas
B1  -1:B1  pas
B2  -2:B1  pas
B3  -3:B1  pas
B4  -4:B1  pas
B5  -5:B1  pas
B6  -6:B1  pas
B7  -7:B1  pas
B8  -8:B1  pas
B9  -9:B1  pas
B10  -10:B1  pas
B11  -11:B1  pas
B12  -12:B1  pas
B13  -13:B1  pas
B14  -14:B1  pas
B15  -15:B1  pas
B16  -16:B1  pas
B17  -17:B1  pas
B18  -18:B1  pas
B19  -19:B1  pas
B20  -20:B1  pas
B21  -21:B1  pas
B22  -22:B1  pas
B23  -23:B1  pas
B24  -24:B1  pas
B25  -25:B1  pas
B26  -26:B1  pas
B27  -27:B1  pas
B28  -28:B1  pas
B29  -29:B1  pas
B30  -30:B1  pas
B31  -31:B1  pas
B32  -32:B1  pas
B33  -33:B1  pas
B34  -34:B1  pas
B35  -35:B1  pas
B36  -36:B1  pas

## WAGO36-234-236  [234-236]
Pads as for 233-136

## WAGO36-255-436-5  [255-436-5]
Pads as for 233-136

## WAGO36-255-436-508  [255-436-508]
Pads as for 233-136

## Footprint 233-136 (pad centres in mm)
WAGO Cage Clamp
drill 1.2 offset: A1 -43.75,2.5; A2 -41.25,2.5; A3 -38.75,2.5; A4 -36.25,2.5; A5 -33.75,2.5; A6 -31.25,2.5; A7 -28.75,2.5; A8 -26.25,2.5; A9 -23.75,2.5; A10 -21.25,2.5; A11 -18.75,2.5; A12 -16.25,2.5; A13 -13.75,2.5; A14 -11.25,2.5; A15 -8.75,2.5; A16 -6.25,2.5; A17 -3.75,2.5; A18 -1.25,2.5; A19 1.25,2.5; A20 3.75,2.5; A21 6.25,2.5; A22 8.75,2.5; A23 11.25,2.5; A24 13.75,2.5; A25 16.25,2.5; A26 18.75,2.5; A27 21.25,2.5; A28 23.75,2.5; A29 26.25,2.5; A30 28.75,2.5; A31 31.25,2.5; A32 33.75,2.5; A33 36.25,2.5; A34 38.75,2.5; A35 41.25,2.5; A36 43.75,2.5; B1 -43.75,-2.5; B2 -41.25,-2.5; B3 -38.75,-2.5; B4 -36.25,-2.5; B5 -33.75,-2.5; B6 -31.25,-2.5; B7 -28.75,-2.5; B8 -26.25,-2.5; B9 -23.75,-2.5; B10 -21.25,-2.5; B11 -18.75,-2.5; B12 -16.25,-2.5; B13 -13.75,-2.5; B14 -11.25,-2.5; B15 -8.75,-2.5; B16 -6.25,-2.5; B17 -3.75,-2.5; B18 -1.25,-2.5; B19 1.25,-2.5; B20 3.75,-2.5; B21 6.25,-2.5; B22 8.75,-2.5; B23 11.25,-2.5; B24 13.75,-2.5; B25 16.25,-2.5; B26 18.75,-2.5; B27 21.25,-2.5; B28 23.75,-2.5; B29 26.25,-2.5; B30 28.75,-2.5; B31 31.25,-2.5; B32 33.75,-2.5; B33 36.25,-2.5; B34 38.75,-2.5; B35 41.25,-2.5; B36 43.75,-2.5

## Footprint 234-236 (pad centres in mm)
WAGO Cage Clamp
drill 1.2 offset: A1 -43.75,2.5; A2 -41.25,2.5; A3 -38.75,2.5; A4 -36.25,2.5; A5 -33.75,2.5; A6 -31.25,2.5; A7 -28.75,2.5; A8 -26.25,2.5; A9 -23.75,2.5; A10 -21.25,2.5; A11 -18.75,2.5; A12 -16.25,2.5; A13 -13.75,2.5; A14 -11.25,2.5; A15 -8.75,2.5; A16 -6.25,2.5; A17 -3.75,2.5; A18 -1.25,2.5; A19 1.25,2.5; A20 3.75,2.5; A21 6.25,2.5; A22 8.75,2.5; A23 11.25,2.5; A24 13.75,2.5; A25 16.25,2.5; A26 18.75,2.5; A27 21.25,2.5; A28 23.75,2.5; A29 26.25,2.5; A30 28.75,2.5; A31 31.25,2.5; A32 33.75,2.5; A33 36.25,2.5; A34 38.75,2.5; A35 41.25,2.5; A36 43.75,2.5; B1 -43.75,-2.5; B2 -41.25,-2.5; B3 -38.75,-2.5; B4 -36.25,-2.5; B5 -33.75,-2.5; B6 -31.25,-2.5; B7 -28.75,-2.5; B8 -26.25,-2.5; B9 -23.75,-2.5; B10 -21.25,-2.5; B11 -18.75,-2.5; B12 -16.25,-2.5; B13 -13.75,-2.5; B14 -11.25,-2.5; B15 -8.75,-2.5; B16 -6.25,-2.5; B17 -3.75,-2.5; B18 -1.25,-2.5; B19 1.25,-2.5; B20 3.75,-2.5; B21 6.25,-2.5; B22 8.75,-2.5; B23 11.25,-2.5; B24 13.75,-2.5; B25 16.25,-2.5; B26 18.75,-2.5; B27 21.25,-2.5; B28 23.75,-2.5; B29 26.25,-2.5; B30 28.75,-2.5; B31 31.25,-2.5; B32 33.75,-2.5; B33 36.25,-2.5; B34 38.75,-2.5; B35 41.25,-2.5; B36 43.75,-2.5

## Footprint 255-436-5 (pad centres in mm)
Cage Clamp, Grid 5.0 mm
drill 1.2 offset: A1 -87.5,0; A2 -82.5,0; A3 -77.5,0; A4 -72.5,0; A5 -67.5,0; A6 -62.5,0; A7 -57.5,0; A8 -52.5,0; A9 -47.5,0; A10 -42.5,0; A11 -37.5,0; A12 -32.5,0; A13 -27.5,0; A14 -22.5,0; A15 -17.5,0; A16 -12.5,0; A17 -7.5,0; A18 -2.5,0; A19 2.5,0; A20 7.5,0; A21 12.5,0; A22 17.5,0; A23 22.5,0; A24 27.5,0; A25 32.5,0; A26 37.5,0; A27 42.5,0; A28 47.5,0; A29 52.5,0; A30 57.5,0; A31 62.5,0; A32 67.5,0; A33 72.5,0; A34 77.5,0; A35 82.5,0; A36 87.5,0; B1 -87.5,-5; B2 -82.5,-5; B3 -77.5,-5; B4 -72.5,-5; B5 -67.5,-5; B6 -62.5,-5; B7 -57.5,-5; B8 -52.5,-5; B9 -47.5,-5; B10 -42.5,-5; B11 -37.5,-5; B12 -32.5,-5; B13 -27.5,-5; B14 -22.5,-5; B15 -17.5,-5; B16 -12.5,-5; B17 -7.5,-5; B18 -2.5,-5; B19 2.5,-5; B20 7.5,-5; B21 12.5,-5; B22 17.5,-5; B23 22.5,-5; B24 27.5,-5; B25 32.5,-5; B26 37.5,-5; B27 42.5,-5; B28 47.5,-5; B29 52.5,-5; B30 57.5,-5; B31 62.5,-5; B32 67.5,-5; B33 72.5,-5; B34 77.5,-5; B35 82.5,-5; B36 87.5,-5

## Footprint 255-436-508 (pad centres in mm)
Cage Clamp, Grid 5.08 mm
drill 1.2 offset: A1 -88.9,0; A2 -83.82,0; A3 -78.74,0; A4 -73.66,0; A5 -68.58,0; A6 -63.5,0; A7 -58.42,0; A8 -53.34,0; A9 -48.26,0; A10 -43.18,0; A11 -38.1,0; A12 -33.02,0; A13 -27.94,0; A14 -22.86,0; A15 -17.78,0; A16 -12.7,0; A17 -7.62,0; A18 -2.54,0; A19 2.54,0; A20 7.62,0; A21 12.7,0; A22 17.78,0; A23 22.86,0; A24 27.94,0; A25 33.02,0; A26 38.1,0; A27 43.18,0; A28 48.26,0; A29 53.34,0; A30 58.42,0; A31 63.5,0; A32 68.58,0; A33 73.66,0; A34 78.74,0; A35 83.82,0; A36 88.9,0; B1 -88.9,-5; B2 -83.82,-5; B3 -78.74,-5; B4 -73.66,-5; B5 -68.58,-5; B6 -63.5,-5; B7 -58.42,-5; B8 -53.34,-5; B9 -48.26,-5; B10 -43.18,-5; B11 -38.1,-5; B12 -33.02,-5; B13 -27.94,-5; B14 -22.86,-5; B15 -17.78,-5; B16 -12.7,-5; B17 -7.62,-5; B18 -2.54,-5; B19 2.54,-5; B20 7.62,-5; B21 12.7,-5; B22 17.78,-5; B23 22.86,-5; B24 27.94,-5; B25 33.02,-5; B26 38.1,-5; B27 43.18,-5; B28 48.26,-5; B29 53.34,-5; B30 58.42,-5; B31 63.5,-5; B32 68.58,-5; B33 73.66,-5; B34 78.74,-5; B35 83.82,-5; B36 88.9,-5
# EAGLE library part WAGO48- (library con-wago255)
WAGO Cage Clamp

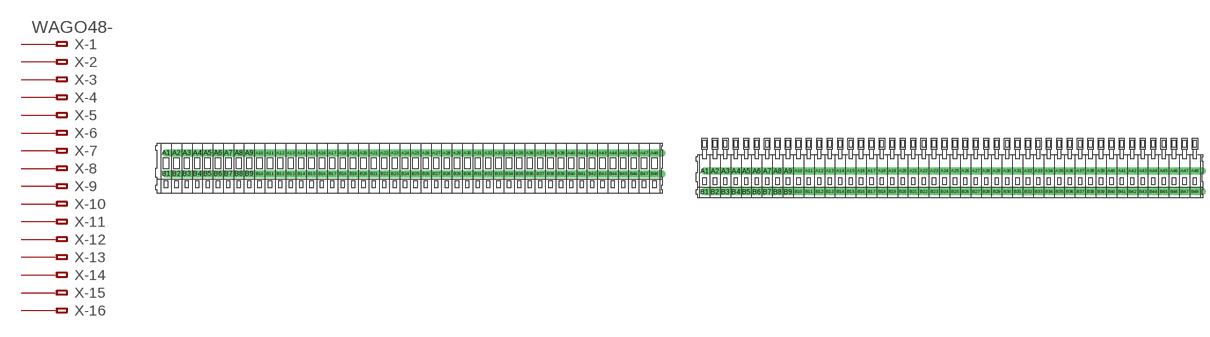
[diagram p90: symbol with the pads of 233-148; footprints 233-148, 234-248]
Designator prefix X; gates -1=KL-1V -2=KL-1 -3=KL-1 -4=KL-1 -5=KL-1 -6=KL-1 -7=KL-1 -8=KL-1 -9=KL-1 -10=KL-1 -11=KL-1 -12=KL-1 -13=KL-1 -14=KL-1 -15=KL-1 -16=KL-1 -17=KL-1 -18=KL-1 -19=KL-1 -20=KL-1 -21=KL-1 -22=KL-1 -23=KL-1 -24=KL-1 -25=KL-1 -26=KL-1 -27=KL-1 -28=KL-1 -29=KL-1 -30=KL-1 -31=KL-1 -32=KL-1 -33=KL-1 -34=KL-1 -35=KL-1 -36=KL-1 -37=KL-1 -38=KL-1 -39=KL-1 -40=KL-1 -41=KL-1 -42=KL-1 -43=KL-1 -44=KL-1 -45=KL-1 -46=KL-1 -47=KL-1 -48=KL-1

## WAGO48-233-148  [233-148]
A1  -1:A1  pas
A2  -2:A1  pas
A3  -3:A1  pas
A4  -4:A1  pas
A5  -5:A1  pas
A6  -6:A1  pas
A7  -7:A1  pas
A8  -8:A1  pas
A9  -9:A1  pas
A10  -10:A1  pas
A11  -11:A1  pas
A12  -12:A1  pas
A13  -13:A1  pas
A14  -14:A1  pas
A15  -15:A1  pas
A16  -16:A1  pas
A17  -17:A1  pas
A18  -18:A1  pas
A19  -19:A1  pas
A20  -20:A1  pas
A21  -21:A1  pas
A22  -22:A1  pas
A23  -23:A1  pas
A24  -24:A1  pas
A25  -25:A1  pas
A26  -26:A1  pas
A27  -27:A1  pas
A28  -28:A1  pas
A29  -29:A1  pas
A30  -30:A1  pas
A31  -31:A1  pas
A32  -32:A1  pas
A33  -33:A1  pas
A34  -34:A1  pas
A35  -35:A1  pas
A36  -36:A1  pas
A37  -37:A1  pas
A38  -38:A1  pas
A39  -39:A1  pas
A40  -40:A1  pas
A41  -41:A1  pas
A42  -42:A1  pas
A43  -43:A1  pas
A44  -44:A1  pas
A45  -45:A1  pas
A46  -46:A1  pas
A47  -47:A1  pas
A48  -48:A1  pas
B1  -1:B1  pas
B2  -2:B1  pas
B3  -3:B1  pas
B4  -4:B1  pas
B5  -5:B1  pas
B6  -6:B1  pas
B7  -7:B1  pas
B8  -8:B1  pas
B9  -9:B1  pas
B10  -10:B1  pas
B11  -11:B1  pas
B12  -12:B1  pas
B13  -13:B1  pas
B14  -14:B1  pas
B15  -15:B1  pas
B16  -16:B1  pas
B17  -17:B1  pas
B18  -18:B1  pas
B19  -19:B1  pas
B20  -20:B1  pas
B21  -21:B1  pas
B22  -22:B1  pas
B23  -23:B1  pas
B24  -24:B1  pas
B25  -25:B1  pas
B26  -26:B1  pas
B27  -27:B1  pas
B28  -28:B1  pas
B29  -29:B1  pas
B30  -30:B1  pas
B31  -31:B1  pas
B32  -32:B1  pas
B33  -33:B1  pas
B34  -34:B1  pas
B35  -35:B1  pas
B36  -36:B1  pas
B37  -37:B1  pas
B38  -38:B1  pas
B39  -39:B1  pas
B40  -40:B1  pas
B41  -41:B1  pas
B42  -42:B1  pas
B43  -43:B1  pas
B44  -44:B1  pas
B45  -45:B1  pas
B46  -46:B1  pas
B47  -47:B1  pas
B48  -48:B1  pas

## WAGO48-234-248  [234-248]
Pads as for 233-148

## WAGO48-255-448-5  [255-448-5]
Pads as for 233-148

## WAGO48-255-448-508  [255-448-508]
Pads as for 233-148

## Footprint 233-148 (pad centres in mm)
WAGO Cage Clamp
drill 1.2 offset: A1 -58.75,2.5; A2 -56.25,2.5; A3 -53.75,2.5; A4 -51.25,2.5; A5 -48.75,2.5; A6 -46.25,2.5; A7 -43.75,2.5; A8 -41.25,2.5; A9 -38.75,2.5; A10 -36.25,2.5; A11 -33.75,2.5; A12 -31.25,2.5; A13 -28.75,2.5; A14 -26.25,2.5; A15 -23.75,2.5; A16 -21.25,2.5; A17 -18.75,2.5; A18 -16.25,2.5; A19 -13.75,2.5; A20 -11.25,2.5; A21 -8.75,2.5; A22 -6.25,2.5; A23 -3.75,2.5; A24 -1.25,2.5; A25 1.25,2.5; A26 3.75,2.5; A27 6.25,2.5; A28 8.75,2.5; A29 11.25,2.5; A30 13.75,2.5; A31 16.25,2.5; A32 18.75,2.5; A33 21.25,2.5; A34 23.75,2.5; A35 26.25,2.5; A36 28.75,2.5; A37 31.25,2.5; A38 33.75,2.5; A39 36.25,2.5; A40 38.75,2.5; A41 41.25,2.5; A42 43.75,2.5; A43 46.25,2.5; A44 48.75,2.5; A45 51.25,2.5; A46 53.75,2.5; A47 56.25,2.5; A48 58.75,2.5; B1 -58.75,-2.5; B2 -56.25,-2.5; B3 -53.75,-2.5; B4 -51.25,-2.5; B5 -48.75,-2.5; B6 -46.25,-2.5; B7 -43.75,-2.5; B8 -41.25,-2.5; B9 -38.75,-2.5; B10 -36.25,-2.5; B11 -33.75,-2.5; B12 -31.25,-2.5; B13 -28.75,-2.5; B14 -26.25,-2.5; B15 -23.75,-2.5; B16 -21.25,-2.5; B17 -18.75,-2.5; B18 -16.25,-2.5; B19 -13.75,-2.5; B20 -11.25,-2.5; B21 -8.75,-2.5; B22 -6.25,-2.5; B23 -3.75,-2.5; B24 -1.25,-2.5; B25 1.25,-2.5; B26 3.75,-2.5; B27 6.25,-2.5; B28 8.75,-2.5; B29 11.25,-2.5; B30 13.75,-2.5; B31 16.25,-2.5; B32 18.75,-2.5; B33 21.25,-2.5; B34 23.75,-2.5; B35 26.25,-2.5; B36 28.75,-2.5; B37 31.25,-2.5; B38 33.75,-2.5; B39 36.25,-2.5; B40 38.75,-2.5; B41 41.25,-2.5; B42 43.75,-2.5; B43 46.25,-2.5; B44 48.75,-2.5; B45 51.25,-2.5; B46 53.75,-2.5; B47 56.25,-2.5; B48 58.75,-2.5

## Footprint 234-248 (pad centres in mm)
WAGO Cage Clamp
drill 1.2 offset: A1 -58.75,2.5; A2 -56.25,2.5; A3 -53.75,2.5; A4 -51.25,2.5; A5 -48.75,2.5; A6 -46.25,2.5; A7 -43.75,2.5; A8 -41.25,2.5; A9 -38.75,2.5; A10 -36.25,2.5; A11 -33.75,2.5; A12 -31.25,2.5; A13 -28.75,2.5; A14 -26.25,2.5; A15 -23.75,2.5; A16 -21.25,2.5; A17 -18.75,2.5; A18 -16.25,2.5; A19 -13.75,2.5; A20 -11.25,2.5; A21 -8.75,2.5; A22 -6.25,2.5; A23 -3.75,2.5; A24 -1.25,2.5; A25 1.25,2.5; A26 3.75,2.5; A27 6.25,2.5; A28 8.75,2.5; A29 11.25,2.5; A30 13.75,2.5; A31 16.25,2.5; A32 18.75,2.5; A33 21.25,2.5; A34 23.75,2.5; A35 26.25,2.5; A36 28.75,2.5; A37 31.25,2.5; A38 33.75,2.5; A39 36.25,2.5; A40 38.75,2.5; A41 41.25,2.5; A42 43.75,2.5; A43 46.25,2.5; A44 48.75,2.5; A45 51.25,2.5; A46 53.75,2.5; A47 56.25,2.5; A48 58.75,2.5; B1 -58.75,-2.5; B2 -56.25,-2.5; B3 -53.75,-2.5; B4 -51.25,-2.5; B5 -48.75,-2.5; B6 -46.25,-2.5; B7 -43.75,-2.5; B8 -41.25,-2.5; B9 -38.75,-2.5; B10 -36.25,-2.5; B11 -33.75,-2.5; B12 -31.25,-2.5; B13 -28.75,-2.5; B14 -26.25,-2.5; B15 -23.75,-2.5; B16 -21.25,-2.5; B17 -18.75,-2.5; B18 -16.25,-2.5; B19 -13.75,-2.5; B20 -11.25,-2.5; B21 -8.75,-2.5; B22 -6.25,-2.5; B23 -3.75,-2.5; B24 -1.25,-2.5; B25 1.25,-2.5; B26 3.75,-2.5; B27 6.25,-2.5; B28 8.75,-2.5; B29 11.25,-2.5; B30 13.75,-2.5; B31 16.25,-2.5; B32 18.75,-2.5; B33 21.25,-2.5; B34 23.75,-2.5; B35 26.25,-2.5; B36 28.75,-2.5; B37 31.25,-2.5; B38 33.75,-2.5; B39 36.25,-2.5; B40 38.75,-2.5; B41 41.25,-2.5; B42 43.75,-2.5; B43 46.25,-2.5; B44 48.75,-2.5; B45 51.25,-2.5; B46 53.75,-2.5; B47 56.25,-2.5; B48 58.75,-2.5

## Footprint 255-448-5 (pad centres in mm)
Cage Clamp, Grid 5.0 mm
drill 1.2 offset: A1 -117.5,0; A2 -112.5,0; A3 -107.5,0; A4 -102.5,0; A5 -97.5,0; A6 -92.5,0; A7 -87.5,0; A8 -82.5,0; A9 -77.5,0; A10 -72.5,0; A11 -67.5,0; A12 -62.5,0; A13 -57.5,0; A14 -52.5,0; A15 -47.5,0; A16 -42.5,0; A17 -37.5,0; A18 -32.5,0; A19 -27.5,0; A20 -22.5,0; A21 -17.5,0; A22 -12.5,0; A23 -7.5,0; A24 -2.5,0; A25 2.5,0; A26 7.5,0; A27 12.5,0; A28 17.5,0; A29 22.5,0; A30 27.5,0; A31 32.5,0; A32 37.5,0; A33 42.5,0; A34 47.5,0; A35 52.5,0; A36 57.5,0; A37 62.5,0; A38 67.5,0; A39 72.5,0; A40 77.5,0; A41 82.5,0; A42 87.5,0; A43 92.5,0; A44 97.5,0; A45 102.5,0; A46 107.5,0; A47 112.5,0; A48 117.5,0; B1 -117.5,-5; B2 -112.5,-5; B3 -107.5,-5; B4 -102.5,-5; B5 -97.5,-5; B6 -92.5,-5; B7 -87.5,-5; B8 -82.5,-5; B9 -77.5,-5; B10 -72.5,-5; B11 -67.5,-5; B12 -62.5,-5; B13 -57.5,-5; B14 -52.5,-5; B15 -47.5,-5; B16 -42.5,-5; B17 -37.5,-5; B18 -32.5,-5; B19 -27.5,-5; B20 -22.5,-5; B21 -17.5,-5; B22 -12.5,-5; B23 -7.5,-5; B24 -2.5,-5; B25 2.5,-5; B26 7.5,-5; B27 12.5,-5; B28 17.5,-5; B29 22.5,-5; B30 27.5,-5; B31 32.5,-5; B32 37.5,-5; B33 42.5,-5; B34 47.5,-5; B35 52.5,-5; B36 57.5,-5; B37 62.5,-5; B38 67.5,-5; B39 72.5,-5; B40 77.5,-5; B41 82.5,-5; B42 87.5,-5; B43 92.5,-5; B44 97.5,-5; B45 102.5,-5; B46 107.5,-5; B47 112.5,-5; B48 117.5,-5

## Footprint 255-448-508 (pad centres in mm)
Cage Clamp, Grid 5.08 mm
drill 1.2 offset: A1 -119.38,0; A2 -114.3,0; A3 -109.22,0; A4 -104.14,0; A5 -99.06,0; A6 -93.98,0; A7 -88.9,0; A8 -83.82,0; A9 -78.74,0; A10 -73.66,0; A11 -68.58,0; A12 -63.5,0; A13 -58.42,0; A14 -53.34,0; A15 -48.26,0; A16 -43.18,0; A17 -38.1,0; A18 -33.02,0; A19 -27.94,0; A20 -22.86,0; A21 -17.78,0; A22 -12.7,0; A23 -7.62,0; A24 -2.54,0; A25 2.54,0; A26 7.62,0; A27 12.7,0; A28 17.78,0; A29 22.86,0; A30 27.94,0; A31 33.02,0; A32 38.1,0; A33 43.18,0; A34 48.26,0; A35 53.34,0; A36 58.42,0; A37 63.5,0; A38 68.58,0; A39 73.66,0; A40 78.74,0; A41 83.82,0; A42 88.9,0; A43 93.98,0; A44 99.06,0; A45 104.14,0; A46 109.22,0; A47 114.3,0; A48 119.38,0; B1 -119.38,-5; B2 -114.3,-5; B3 -109.22,-5; B4 -104.14,-5; B5 -99.06,-5; B6 -93.98,-5; B7 -88.9,-5; B8 -83.82,-5; B9 -78.74,-5; B10 -73.66,-5; B11 -68.58,-5; B12 -63.5,-5; B13 -58.42,-5; B14 -53.34,-5; B15 -48.26,-5; B16 -43.18,-5; B17 -38.1,-5; B18 -33.02,-5; B19 -27.94,-5; B20 -22.86,-5; B21 -17.78,-5; B22 -12.7,-5; B23 -7.62,-5; B24 -2.54,-5; B25 2.54,-5; B26 7.62,-5; B27 12.7,-5; B28 17.78,-5; B29 22.86,-5; B30 27.94,-5; B31 33.02,-5; B32 38.1,-5; B33 43.18,-5; B34 48.26,-5; B35 53.34,-5; B36 58.42,-5; B37 63.5,-5; B38 68.58,-5; B39 73.66,-5; B40 78.74,-5; B41 83.82,-5; B42 88.9,-5; B43 93.98,-5; B44 99.06,-5; B45 104.14,-5; B46 109.22,-5; B47 114.3,-5; B48 119.38,-5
